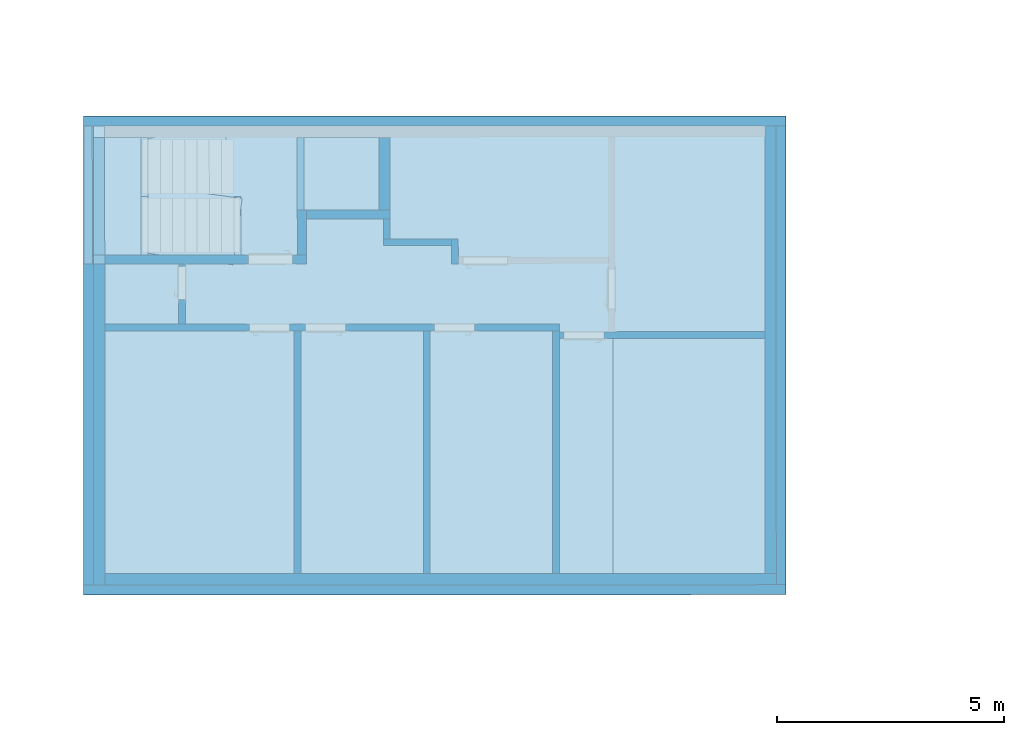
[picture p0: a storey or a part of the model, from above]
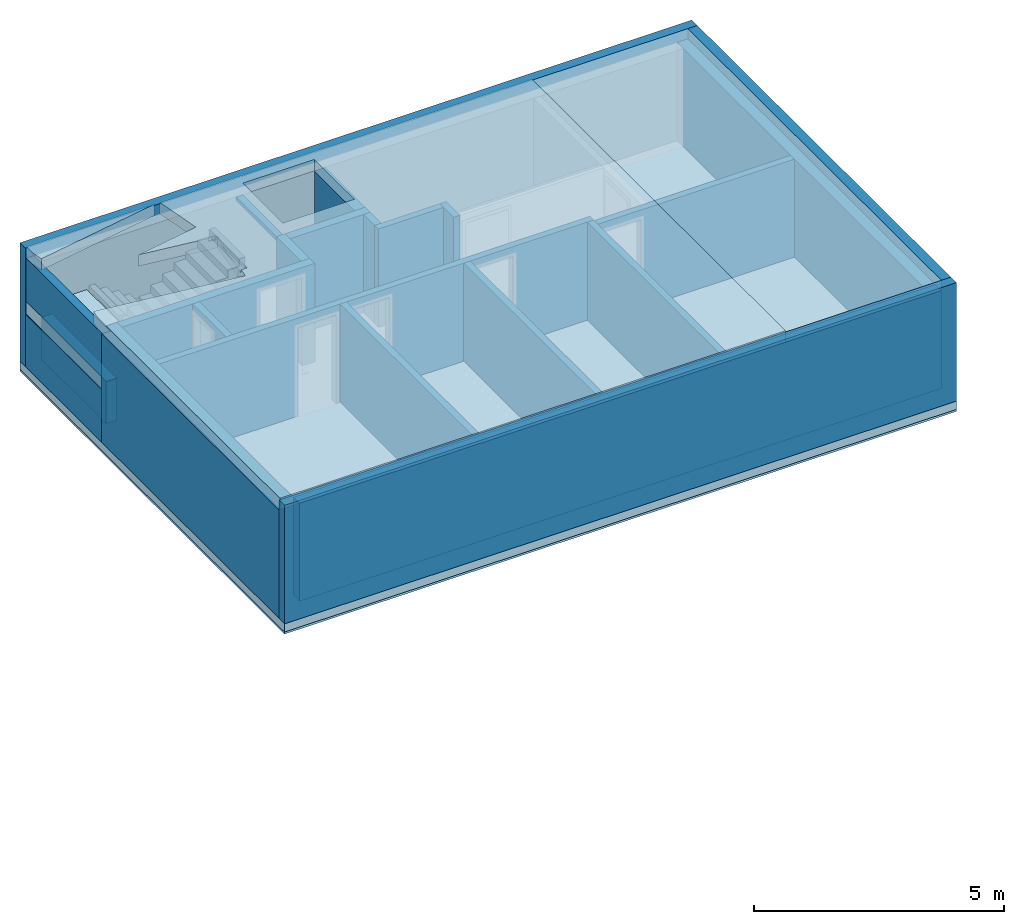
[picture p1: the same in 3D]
Properties of the parts of a building model (IFC2X3), part 1 of 2

# File
Description: no view
File name: I.ifc
Time: 2026-08-27T15:51:39
Author: Besar Asani
Organization: No Organization
Written by: ODA SDAI 25.4
Authorization: b.asani

# IfcProject, 00'000 - Besar Asani
AllplanAttributes - Bauherr: Bauherr Name; Architekt: Architekt Name; Bauort: PLZ und Ort; Bauunternehmer Straße: Bauunternehmer Strasse; Bauunternehmer Plz/Ort: Bauunternehmer PLZ Ort; Bauherr Straße: Bauherr Strasse; Bauherr Plz/Ort: Bauherr PLZ Ort; Architekt Straße: Architekt Strasse; Architekt Plz/Ort: Architekt PLZ Ort; Projektbeschreibung: Projektbeschreibung; Bauunternehmer: Bauunternehmer Name

# IfcSite, Modelle auf dem Nullpunkt
RefLatitude: 48, 8, 10, 320000; RefLongitude: 11, 41, 19, 320000

# IfcBuildingStorey (5)
In: I
Elevation: 0 m
Name
UG
EG
1.OG
2.OG
3.OG

# IfcBeam (29)
AllplanAttributes - 2D Interaktion: yes; Aussenbauteil: yes; Attributset-Objekt: Beam; Abrechnungsart: m³; Objektname: Unterzug
BeamCommon - Status: Neubau
Pset_BeamCommon - LoadBearing: yes
Name | In | Material = AllplanAttributes, Material = Traduction matériau | Gewerk | Allright_Bauteil_ID
 | UG | Béton | Betonarbeiten | 7503Unz0000000245
 | 3.OG | Bois | Zimmer- und Holzbauarbeiten | 7507Unz0000000322
 | 3.OG | Bois | Zimmer- und Holzbauarbeiten | 7507Unz0000000292
 | 3.OG | Bois | Zimmer- und Holzbauarbeiten | 7507Unz0000000282
 | 3.OG | Bois | Zimmer- und Holzbauarbeiten | 7507Unz0000000326
 | 3.OG | Bois | Zimmer- und Holzbauarbeiten | 7507Unz0000000276
 | 3.OG | Bois | Zimmer- und Holzbauarbeiten | 7507Unz0000000314
 | 3.OG | Bois | Zimmer- und Holzbauarbeiten | 7507Unz0000000316
 | 3.OG | Bois | Zimmer- und Holzbauarbeiten | 7507Unz0000000310
 | 3.OG | Bois | Zimmer- und Holzbauarbeiten | 7507Unz0000000272
 | 3.OG | Bois | Zimmer- und Holzbauarbeiten | 7507Unz0000000274
 | 3.OG | Bois | Zimmer- und Holzbauarbeiten | 7507Unz0000000300
 | 3.OG | Bois | Zimmer- und Holzbauarbeiten | 7507Unz0000000280
 | 3.OG | Bois | Zimmer- und Holzbauarbeiten | 7507Unz0000000286
 | 3.OG | Béton | Betonarbeiten | 7507Unz0000000324
 | 3.OG | Bois | Zimmer- und Holzbauarbeiten | 7507Unz0000000306
 | 3.OG | Bois | Zimmer- und Holzbauarbeiten | 7507Unz0000000318
 | 3.OG | Bois | Zimmer- und Holzbauarbeiten | 7507Unz0000000312
 | 3.OG | Bois | Zimmer- und Holzbauarbeiten | 7507Unz0000000320
 | 3.OG | Bois | Zimmer- und Holzbauarbeiten | 7507Unz0000000296
 | 3.OG | Bois | Zimmer- und Holzbauarbeiten | 7507Unz0000000290
 | 3.OG | Bois | Zimmer- und Holzbauarbeiten | 7507Unz0000000308
 | 3.OG | Bois | Zimmer- und Holzbauarbeiten | 7507Unz0000000284
 | 3.OG | Bois | Zimmer- und Holzbauarbeiten | 7507Unz0000000278
 | 3.OG | Bois | Zimmer- und Holzbauarbeiten | 7507Unz0000000270
 | 3.OG | Bois | Zimmer- und Holzbauarbeiten | 7507Unz0000000304
 | 3.OG | Bois | Zimmer- und Holzbauarbeiten | 7507Unz0000000298
 | 3.OG | Bois | Zimmer- und Holzbauarbeiten | 7507Unz0000000294
 | 3.OG | Bois | Zimmer- und Holzbauarbeiten | 7507Unz0000000288

# IfcBuildingElementProxy (68)
Name | In | Objektname | Bezeichnung | Attributset-Objekt | Allright_Bauteil_ID | Abrechnungsart | V6 (m) = V7 (m) = V8 (m) = V9 | Programmversion | Plugin_Bezeichnung | Plugin_Objektname | Glasanteil_berücksichtigen | Version | Abrechnungsart (2) | GlassSurface | HeightWindowSillOutside | HeightWindowSillInside | OffsetOpeningBottom = OffsetOpeningTop = OffsetOpeningLeft = OffsetOpeningRight | DeductionOpeningBottom | DeductionOpeningLeft | DeductionOpeningRight | DeductionOpeningTop
Kontrollpunkt | UG | Kontrollpunkt | Kontrollpunkt | Body | 7503Kop0000000006 | m³ | AllplanAttributes - Text1: X = 2695881.75; Text2: Y = 1261014.30; Typ: Kontrollpunkt; Elementbezeichnung: Kontrollpunkt; Barrierefrei: no; öffentlich zugänglich: no; BuildingElementProxyCommon - Status: Neubau; Tragendes Bauteil: no
Kontrollpunkt | UG | Kontrollpunkt | Kontrollpunkt | Body | 7503Kop0000000008 | m³ | AllplanAttributes - Text1: X = 2695833.95; Text2: Y = 1261009.75; Typ: Kontrollpunkt; Elementbezeichnung: Kontrollpunkt; Barrierefrei: no; öffentlich zugänglich: no; X_Koordinate: 0 m; Y_Koordinate: 0 m; Achsenendpunkt (X): 0 m; BuildingElementProxyCommon - Status: Neubau; Tragendes Bauteil: no
1flg Weiß UZ außen | UG | Türmakro, -SmartPart | 1flg Weiß UZ außen | Door | 7503Mak0000000034 | St | 0 | 3.0 | MainObject | SmartPartCompressed | 0 | 8.0 | St | 0 | 0 | 0 | 0 | 0 | 20 | 20 | 20 | AllplanAttributes - Behindertengerecht: no; Selbstschliessend: no; DoorCommon - Rauchschutz: no; Notausgang: no; Antrieb: no
1flg Weiß UZ außen | UG | Türmakro, -SmartPart | 1flg Weiß UZ außen | Door | 7503Mak0000000064 | St | 0 | 3.0 | MainObject | SmartPartCompressed | 0 | 8.0 | St | 0 | 0 | 0 | 0 | 0 | 20 | 20 | 20 | AllplanAttributes - Behindertengerecht: no; Selbstschliessend: no; DoorCommon - Rauchschutz: no; Notausgang: no; Antrieb: no
1flg Weiß UZ außen | UG | Türmakro, -SmartPart | 1flg Weiß UZ außen | Door | 7503Mak0000000097 | St | 0 | 3.0 | MainObject | SmartPartCompressed | 0 | 8.0 | St | 0 | 0 | 0 | 0 | 0 | 20 | 20 | 20 | AllplanAttributes - Behindertengerecht: no; Selbstschliessend: no; DoorCommon - Rauchschutz: no; Notausgang: no; Antrieb: no
1flg Weiß UZ außen | UG | Türmakro, -SmartPart | 1flg Weiß UZ außen | Door | 7503Mak0000000138 | St | 0 | 3.0 | MainObject | SmartPartCompressed | 0 | 8.0 | St | 0 | 0 | 0 | 0 | 0 | 20 | 20 | 20 | AllplanAttributes - Behindertengerecht: no; Selbstschliessend: no; DoorCommon - Rauchschutz: no; Notausgang: no; Antrieb: no
1flg Weiß UZ außen | UG | Türmakro, -SmartPart | 1flg Weiß UZ außen | Door | 7503Mak0000000157 | St | 0 | 3.0 | MainObject | SmartPartCompressed | 0 | 8.0 | St | 0 | 0 | 0 | 0 | 0 | 20 | 20 | 20 | AllplanAttributes - Behindertengerecht: no; Selbstschliessend: no; DoorCommon - Rauchschutz: no; Notausgang: no; Antrieb: no
1flg Weiß UZ außen | UG | Türmakro, -SmartPart | 1flg Weiß UZ außen | Door | 7503Mak0000000176 | St | 0 | 3.0 | MainObject | SmartPartCompressed | 0 | 8.0 | St | 0 | 0 | 0 | 0 | 0 | 20 | 20 | 20 | AllplanAttributes - Behindertengerecht: no; Selbstschliessend: no; DoorCommon - Rauchschutz: no; Notausgang: no; Antrieb: no
1flg Weiß UZ außen | UG | Türmakro, -SmartPart | 1flg Weiß UZ außen | Door | 7503Mak0000000197 | St | 0 | 3.0 | MainObject | SmartPartCompressed | 0 | 8.0 | St | 0 | 0 | 0 | 0 | 0 | 20 | 20 | 20 | AllplanAttributes - Behindertengerecht: no; Selbstschliessend: no; DoorCommon - Rauchschutz: no; Notausgang: no; Antrieb: no
1flg Weiß UZ außen | UG | Türmakro, -SmartPart | 1flg Weiß UZ außen | Door | 7503Mak0000000221 | St | 0 | 3.0 | MainObject | SmartPartCompressed | 0 | 8.0 | St | 0 | 0 | 0 | 0 | 0 | 20 | 20 | 20 | AllplanAttributes - Behindertengerecht: no; Selbstschliessend: no; DoorCommon - Rauchschutz: no; Notausgang: no; Antrieb: no
 | UG | Mengenkörper |  | Body | 7503Kop0000000226 | m³
 | UG | Mengenkörper |  | Body | 7503Kop0000000228 | m³
 | UG | Mengenkörper |  | Body | 7503Kop0000000230 | m³
 | UG | Mengenkörper |  | Body | 7503Kop0000000232 | m³
1flg Weiß Oberlicht | EG | Türmakro, -SmartPart | 1flg Weiß Oberlicht | Door | 7504Mak0000000036 | St | 0 | 3.0 | MainObject | SmartPartCompressed | 0 | 8.0 | St | 2.02 | 0 | 0 | 0 | 250 | 120 | 120 | 100 | AllplanAttributes - Behindertengerecht: no; Selbstschliessend: no; DoorCommon - Rauchschutz: no; Notausgang: no; Antrieb: no
2flg Weiß Stulp | EG | Fenstermakro, -SmartPart | 2flg Weiß Stulp | Window | 7504Mak0000000062 | St | 0 | 3.0 | MainObject | SmartPartCompressed | 100 | 8.0 | St | 1.67895 | 150 | 30 | 0 | 70 | 70 | 70 | 70 | AllplanAttributes - Fensterbank aussen: no; WindowCommon - Rauchschutz: no; Notausgang: no; Antrieb: no; Fensterbank innen: no
1flg Weiß UZ außen | EG | Türmakro, -SmartPart | 1flg Weiß UZ außen | Door | 7504Mak0000000115 | St | 0 | 3.0 | MainObject | SmartPartCompressed | 0 | 8.0 | St | 0 | 0 | 0 | 0 | 0 | 20 | 20 | 20 | AllplanAttributes - Behindertengerecht: no; Selbstschliessend: no; DoorCommon - Rauchschutz: no; Notausgang: no; Antrieb: no
2flg Weiß Stulp | EG | Fenstermakro, -SmartPart | 2flg Weiß Stulp | Window | 7504Mak0000000141 | St | 0 | 3.0 | MainObject | SmartPartCompressed | 100 | 8.0 | St | 2.14047 | 130 | 30 | 0 | 150 | 70 | 70 | 150 | AllplanAttributes - Fensterbank aussen: no; WindowCommon - Rauchschutz: no; Notausgang: no; Antrieb: no; Fensterbank innen: no
2flg Weiß Stulp | EG | Fenstermakro, -SmartPart | 2flg Weiß Stulp | Window | 7504Mak0000000165 | St | 0 | 3.0 | MainObject | SmartPartCompressed | 100 | 8.0 | St | 2.14047 | 130 | 30 | 0 | 150 | 70 | 70 | 150 | AllplanAttributes - Fensterbank aussen: no; WindowCommon - Rauchschutz: no; Notausgang: no; Antrieb: no; Fensterbank innen: no
1flg Weiß UZ außen | EG | Türmakro, -SmartPart | 1flg Weiß UZ außen | Door | 7504Mak0000000221 | St | 0 | 3.0 | MainObject | SmartPartCompressed | 0 | 8.0 | St | 0 | 0 | 0 | 0 | 0 | 20 | 20 | 20 | AllplanAttributes - Behindertengerecht: no; Selbstschliessend: no; DoorCommon - Rauchschutz: no; Notausgang: no; Antrieb: no
1flg Weiß UZ außen | EG | Türmakro, -SmartPart | 1flg Weiß UZ außen | Door | 7504Mak0000000242 | St | 0 | 3.0 | MainObject | SmartPartCompressed | 0 | 8.0 | St | 0 | 0 | 0 | 0 | 0 | 20 | 20 | 20 | AllplanAttributes - Behindertengerecht: no; Selbstschliessend: no; DoorCommon - Rauchschutz: no; Notausgang: no; Antrieb: no
1flg Weiß UZ außen | EG | Türmakro, -SmartPart | 1flg Weiß UZ außen | Door | 7504Mak0000000261 | St | 0 | 3.0 | MainObject | SmartPartCompressed | 0 | 8.0 | St | 0 | 0 | 0 | 0 | 0 | 20 | 20 | 20 | AllplanAttributes - Behindertengerecht: no; Selbstschliessend: no; DoorCommon - Rauchschutz: no; Notausgang: no; Antrieb: no
1flg Weiß UZ außen | EG | Türmakro, -SmartPart | 1flg Weiß UZ außen | Door | 7504Mak0000000282 | St | 0 | 3.0 | MainObject | SmartPartCompressed | 0 | 8.0 | St | 0 | 0 | 0 | 0 | 0 | 20 | 20 | 20 | AllplanAttributes - Behindertengerecht: no; Selbstschliessend: no; DoorCommon - Rauchschutz: no; Notausgang: no; Antrieb: no
2flg Weiß Stulp | EG | Fenstermakro, -SmartPart | 2flg Weiß Stulp | Window | 7504Mak0000000314 | St | 0 | 3.0 | MainObject | SmartPartCompressed | 100 | 8.0 | St | 2.8788 | 150 | 30 | 0 | 70 | 70 | 70 | 70 | AllplanAttributes - Fensterbank aussen: no; WindowCommon - Rauchschutz: no; Notausgang: no; Antrieb: no; Fensterbank innen: no
 | EG | Mengenkörper |  | Body | 7504Kop0000000324 | m³
 | EG | Mengenkörper |  | Body | 7504Kop0000000326 | m³
 | EG | Mengenkörper |  | Body | 7504Kop0000000328 | m³
 | EG | Mengenkörper |  | Body | 7504Kop0000000330 | m³
 | EG | Mengenkörper |  | Body | 7504Kop0000000335 | m³
2flg Weiß Stulp | 1.OG | Fenstermakro, -SmartPart | 2flg Weiß Stulp | Window | 7505Mak0000000021 | St | 0 | 3.0 | MainObject | SmartPartCompressed | 100 | 8.0 | St | 0.63443 | 0 | 0 | 0 | 150 | 150 | 150 | 150 | AllplanAttributes - Fensterbank aussen: no; WindowCommon - Rauchschutz: no; Notausgang: no; Antrieb: no; Fensterbank innen: no
2flg Weiß Stulp | 1.OG | Fenstermakro, -SmartPart | 2flg Weiß Stulp | Window | 7505Mak0000000047 | St | 0 | 3.0 | MainObject | SmartPartCompressed | 100 | 8.0 | St | 1.31118 | 130 | 30 | 0 | 150 | 70 | 70 | 210 | AllplanAttributes - Fensterbank aussen: no; WindowCommon - Rauchschutz: no; Notausgang: no; Antrieb: no; Fensterbank innen: no
1flg Weiß UZ außen | 1.OG | Türmakro, -SmartPart | 1flg Weiß UZ außen | Door | 7505Mak0000000091 | St | 0 | 3.0 | MainObject | SmartPartCompressed | 0 | 8.0 | St | 0 | 0 | 0 | 0 | 0 | 20 | 20 | 20 | AllplanAttributes - Behindertengerecht: no; Selbstschliessend: no; DoorCommon - Rauchschutz: no; Notausgang: no; Antrieb: no
1flg Weiß UZ außen | 1.OG | Türmakro, -SmartPart | 1flg Weiß UZ außen | Door | 7505Mak0000000121 | St | 0 | 3.0 | MainObject | SmartPartCompressed | 0 | 8.0 | St | 0 | 0 | 0 | 0 | 0 | 20 | 20 | 20 | AllplanAttributes - Behindertengerecht: no; Selbstschliessend: no; DoorCommon - Rauchschutz: no; Notausgang: no; Antrieb: no
1flg Weiß UZ außen | 1.OG | Türmakro, -SmartPart | 1flg Weiß UZ außen | Door | 7505Mak0000000142 | St | 0 | 3.0 | MainObject | SmartPartCompressed | 0 | 8.0 | St | 0 | 0 | 0 | 0 | 0 | 20 | 20 | 20 | AllplanAttributes - Behindertengerecht: no; Selbstschliessend: no; DoorCommon - Rauchschutz: no; Notausgang: no; Antrieb: no
1flg Weiß UZ außen | 1.OG | Türmakro, -SmartPart | 1flg Weiß UZ außen | Door | 7505Mak0000000178 | St | 0 | 3.0 | MainObject | SmartPartCompressed | 0 | 8.0 | St | 0 | 0 | 0 | 0 | 0 | 20 | 20 | 20 | AllplanAttributes - Behindertengerecht: no; Selbstschliessend: no; DoorCommon - Rauchschutz: no; Notausgang: no; Antrieb: no
1flg Weiß UZ außen | 1.OG | Türmakro, -SmartPart | 1flg Weiß UZ außen | Door | 7505Mak0000000197 | St | 0 | 3.0 | MainObject | SmartPartCompressed | 0 | 8.0 | St | 0 | 0 | 0 | 0 | 0 | 20 | 20 | 20 | AllplanAttributes - Behindertengerecht: no; Selbstschliessend: no; DoorCommon - Rauchschutz: no; Notausgang: no; Antrieb: no
2flg Weiß Stulp | 1.OG | Fenstermakro, -SmartPart | 2flg Weiß Stulp | Window | 7505Mak0000000223 | St | 0 | 3.0 | MainObject | SmartPartCompressed | 100 | 8.0 | St | 2.29779 | 130 | 30 | 0 | 150 | 70 | 70 | 220 | AllplanAttributes - Fensterbank aussen: no; WindowCommon - Rauchschutz: no; Notausgang: no; Antrieb: no; Fensterbank innen: no
2flg Weiß Stulp | 1.OG | Fenstermakro, -SmartPart | 2flg Weiß Stulp | Window | 7505Mak0000000247 | St | 0 | 3.0 | MainObject | SmartPartCompressed | 100 | 8.0 | St | 2.29779 | 130 | 30 | 0 | 150 | 70 | 70 | 220 | AllplanAttributes - Fensterbank aussen: no; WindowCommon - Rauchschutz: no; Notausgang: no; Antrieb: no; Fensterbank innen: no
2flg Weiß Stulp | 1.OG | Fenstermakro, -SmartPart | 2flg Weiß Stulp | Door | 7505Mak0000000271 | St | 0 | 3.0 | MainObject | SmartPartCompressed | 100 | 8.0 | St | 2.29779 | 130 | 30 | 0 | 150 | 70 | 70 | 220 | DoorCommon - Rauchschutz: no; Notausgang: no; Antrieb: no; AllplanAttributes - Fensterbank außen: no; Fensterbank innen: no
1flg Weiß Blockzarge | 1.OG | Fenstermakro, -SmartPart | 1flg Weiß Blockzarge | Window | 7505Mak0000000302 | St | 0 | 3.0 | MainObject | SmartPartCompressed | 0 | 8.0 | St | 6.9847 | 0 | 0 | 0 | 0 | 70 | 70 | 70 | AllplanAttributes - Barrierefrei: no; Selbstschließend: no; WindowCommon - Rauchschutz: no; Notausgang: no; Antrieb: no
 | 1.OG | Mengenkörper |  | Body | 7505Kop0000000310 | m³
 | 1.OG | Mengenkörper |  | Body | 7505Kop0000000312 | m³
 | 1.OG | Mengenkörper |  | Body | 7505Kop0000000314 | m³
 | 1.OG | Mengenkörper |  | Body | 7505Kop0000000316 | m³
1flg Weiß UZ außen | 2.OG | Türmakro, -SmartPart | 1flg Weiß UZ außen | Door | 7506Mak0000000054 | St | 0 | 3.0 | MainObject | SmartPartCompressed | 0 | 8.0 | St | 0 | 0 | 0 | 0 | 0 | 20 | 20 | 20 | AllplanAttributes - Behindertengerecht: no; Selbstschliessend: no; DoorCommon - Rauchschutz: no; Notausgang: no; Antrieb: no
1flg Weiß UZ außen | 2.OG | Türmakro, -SmartPart | 1flg Weiß UZ außen | Door | 7506Mak0000000081 | St | 0 | 3.0 | MainObject | SmartPartCompressed | 0 | 8.0 | St | 0 | 0 | 0 | 0 | 0 | 20 | 20 | 20 | AllplanAttributes - Behindertengerecht: no; Selbstschliessend: no; DoorCommon - Rauchschutz: no; Notausgang: no; Antrieb: no
1flg Weiß UZ außen | 2.OG | Türmakro, -SmartPart | 1flg Weiß UZ außen | Door | 7506Mak0000000102 | St | 0 | 3.0 | MainObject | SmartPartCompressed | 0 | 8.0 | St | 0 | 0 | 0 | 0 | 0 | 20 | 20 | 20 | AllplanAttributes - Behindertengerecht: no; Selbstschliessend: no; DoorCommon - Rauchschutz: no; Notausgang: no; Antrieb: no
1flg Weiß UZ außen | 2.OG | Türmakro, -SmartPart | 1flg Weiß UZ außen | Door | 7506Mak0000000135 | St | 0 | 3.0 | MainObject | SmartPartCompressed | 0 | 8.0 | St | 0 | 0 | 0 | 0 | 0 | 20 | 20 | 20 | AllplanAttributes - Behindertengerecht: no; Selbstschliessend: no; DoorCommon - Rauchschutz: no; Notausgang: no; Antrieb: no
1flg Weiß UZ außen | 2.OG | Türmakro, -SmartPart | 1flg Weiß UZ außen | Door | 7506Mak0000000154 | St | 0 | 3.0 | MainObject | SmartPartCompressed | 0 | 8.0 | St | 0 | 0 | 0 | 0 | 0 | 20 | 20 | 20 | AllplanAttributes - Behindertengerecht: no; Selbstschliessend: no; DoorCommon - Rauchschutz: no; Notausgang: no; Antrieb: no
2flg Weiß Stulp | 2.OG | Fenstermakro, -SmartPart | 2flg Weiß Stulp | Window | 7506Mak0000000180 | St | 0 | 3.0 | MainObject | SmartPartCompressed | 100 | 8.0 | St | 1.31118 | 130 | 30 | 0 | 150 | 70 | 70 | 210 | AllplanAttributes - Fensterbank aussen: no; WindowCommon - Rauchschutz: no; Notausgang: no; Antrieb: no; Fensterbank innen: no
2flg Weiß Stulp | 2.OG | Fenstermakro, -SmartPart | 2flg Weiß Stulp | Window | 7506Mak0000000206 | St | 0 | 3.0 | MainObject | SmartPartCompressed | 100 | 8.0 | St | 2.2788 | 130 | 30 | 0 | 150 | 70 | 70 | 230 | AllplanAttributes - Fensterbank aussen: no; WindowCommon - Rauchschutz: no; Notausgang: no; Antrieb: no; Fensterbank innen: no
2flg Weiß Stulp | 2.OG | Fenstermakro, -SmartPart | 2flg Weiß Stulp | Window | 7506Mak0000000230 | St | 0 | 3.0 | MainObject | SmartPartCompressed | 100 | 8.0 | St | 2.2788 | 130 | 30 | 0 | 150 | 70 | 70 | 230 | AllplanAttributes - Fensterbank aussen: no; WindowCommon - Rauchschutz: no; Notausgang: no; Antrieb: no; Fensterbank innen: no
2flg Weiß Stulp | 2.OG | Fenstermakro, -SmartPart | 2flg Weiß Stulp | Door | 7506Mak0000000254 | St | 0 | 3.0 | MainObject | SmartPartCompressed | 100 | 8.0 | St | 2.2788 | 130 | 30 | 0 | 150 | 70 | 70 | 230 | DoorCommon - Rauchschutz: no; Notausgang: no; Antrieb: no; AllplanAttributes - Fensterbank außen: no; Fensterbank innen: no
2flg Weiß Stulp | 2.OG | Fenstermakro, -SmartPart | 2flg Weiß Stulp | Door | 7506Mak0000000285 | St | 0 | 3.0 | MainObject | SmartPartCompressed | 100 | 8.0 | St | 1.2183 | 130 | 30 | 0 | 70 | 70 | 70 | 200 | DoorCommon - Rauchschutz: no; Notausgang: no; Antrieb: no; AllplanAttributes - Fensterbank außen: no; Fensterbank innen: no
1flg Weiß Blockzarge | 2.OG | Fenstermakro, -SmartPart | 1flg Weiß Blockzarge | Window | 7506Mak0000000329 | St | 0 | 3.0 | MainObject | SmartPartCompressed | 0 | 8.0 | St | 6.2837 | 0 | 0 | 0 | 0 | 70 | 70 | 70 | AllplanAttributes - Barrierefrei: no; Selbstschließend: no; WindowCommon - Rauchschutz: no; Notausgang: no; Antrieb: no
 | 2.OG | Mengenkörper |  | Body | 7506Kop0000000340 | m³
 | 2.OG | Mengenkörper |  | Body | 7506Kop0000000342 | m³
 | 2.OG | Mengenkörper |  | Body | 7506Kop0000000347 | m³
 | 2.OG | Mengenkörper |  | Body | 7506Kop0000000349 | m³
1flg Weiß UZ außen | 3.OG | Türmakro, -SmartPart | 1flg Weiß UZ außen | Door | 7507Mak0000000033 | St | 0 | 3.0 | MainObject | SmartPartCompressed | 0 | 8.0 | St | 0 | 0 | 0 | 0 | 0 | 20 | 20 | 20 | AllplanAttributes - Behindertengerecht: no; Selbstschliessend: no; DoorCommon - Rauchschutz: no; Notausgang: no; Antrieb: no
2flg Weiß Stulp | 3.OG | Fenstermakro, -SmartPart | 2flg Weiß Stulp | Window | 7507Mak0000000044 | St | 0 | 3.0 | MainObject | SmartPartCompressed | 100 | 8.0 | St | 0 | 0 | 0 | 0 | 175 | 0 | 350 | 350 | AllplanAttributes - Fensterbank aussen: no; WindowCommon - Rauchschutz: no; Notausgang: no; Antrieb: no; Fensterbank innen: no
2flg Weiß Stulp | 3.OG | Fenstermakro, -SmartPart | 2flg Weiß Stulp | Window | 7507Mak0000000073 | St | 0 | 3.0 | MainObject | SmartPartCompressed | 100 | 8.0 | St | 1.19196 | 130 | 30 | 0 | 120 | 70 | 70 | 220 | AllplanAttributes - Fensterbank aussen: no; WindowCommon - Rauchschutz: no; Notausgang: no; Antrieb: no; Fensterbank innen: no
2flg Weiß Stulp | 3.OG | Fenstermakro, -SmartPart | 2flg Weiß Stulp | Window | 7507Mak0000000119 | St | 0 | 3.0 | MainObject | SmartPartCompressed | 100 | 8.0 | St | 0.6308 | 130 | 30 | 0 | 200 | 120 | 120 | 220 | AllplanAttributes - Fensterbank aussen: no; WindowCommon - Rauchschutz: no; Notausgang: no; Antrieb: no; Fensterbank innen: no
2flg Weiß Stulp | 3.OG | Fenstermakro, -SmartPart | 2flg Weiß Stulp | Window | 7507Mak0000000139 | St | 0 | 3.0 | MainObject | SmartPartCompressed | 100 | 8.0 | St | 1.7596 | 155 | 30 | 0 | 200 | 120 | 120 | 250 | AllplanAttributes - Fensterbank aussen: no; WindowCommon - Rauchschutz: no; Notausgang: no; Antrieb: no; Fensterbank innen: no
1flg Weiß UZ außen | 3.OG | Türmakro, -SmartPart | 1flg Weiß UZ außen | Door | 7507Mak0000000218 | St | 0 | 3.0 | MainObject | SmartPartCompressed | 0 | 8.0 | St | 0 | 0 | 0 | 0 | 80 | 20 | 20 | 20 | AllplanAttributes - Behindertengerecht: no; Selbstschliessend: no; DoorCommon - Rauchschutz: no; Notausgang: no; Antrieb: no
 | 3.OG | Erweitertes Element |  | Body | 7507Kop0000000226 | m³ | AllplanAttributes - Gewerk: Betonarbeiten
1flg Weiß UZ außen | 3.OG | Türmakro, -SmartPart | 1flg Weiß UZ außen | Door | 7507Mak0000000247 | St | 0 | 3.0 | MainObject | SmartPartCompressed | 0 | 8.0 | St | 1.9339 | 0 | 0 | 0 | 0 | 20 | 20 | 20 | AllplanAttributes - Behindertengerecht: no; Selbstschliessend: no; DoorCommon - Rauchschutz: no; Notausgang: no; Antrieb: no
2flg Weiß Stulp | 3.OG | SmartPart | 2flg Weiß Stulp | Body | 7507Mak0000000262 | St | 0 | 3.0 | MainObject | SmartPartCompressed | 100 | 8.0 | St | AllplanAttributes - Fensterbank außen: no; Fensterbank innen: no; Glasfläche: 0; Einbauhöhe_Fensterbank_Außen: 0.13 m; Einbauhöhe_Fensterbank_Innen: 0 m; Abstand_Öffn_Unten: 0 m; Abstand_Öffn_Oben: 0 m; Abstand_Öffn_Links: 0 m; Abstand_Öffn_Rechts: 0 m; Abzug_Öffn_Unten: 0 m; Abzug_Öffn_Links: 0 m; Abzug_Öffn_Rechts: 0 m; Abzug_Öffn_Oben: 0 m; Rauchschutz: no; Notausgang: no; Antrieb: no

# IfcBuildingElementProxy: DOOR (5)
AllplanAttributes - V6: 0 m; V7: 0 m; V8: 0 m; V9: 0; Programmversion: 3.0; Bezeichnung: 1flg Weiß Blockzarge; Plugin_Bezeichnung: MainObject; Plugin_Objektname: SmartPartCompressed; Glasanteil_berücksichtigen: 0; Version: 8.0; Attributset-Objekt: Door; Abrechnungsart (2): St; HeightWindowSillOutside: 0; HeightWindowSillInside: 0; OffsetOpeningBottom: 0; OffsetOpeningTop: 0; OffsetOpeningLeft: 0; OffsetOpeningRight: 0; Behindertengerecht: no; Selbstschliessend: no; Abrechnungsart: St
DoorCommon - Rauchschutz: no; Notausgang: no; Antrieb: no
Name | In | Objektname | GlassSurface | DeductionOpeningBottom | DeductionOpeningLeft = DeductionOpeningRight | DeductionOpeningTop | Allright_Bauteil_ID
1flg Weiß Blockzarge | EG | Türmakro, -SmartPart | 7.1067 | 0 | 70 | 70 | 7504Mak0000000183
1flg Weiß Blockzarge | 2.OG | Fenstermakro, -SmartPart | 1.7765 | 200 | 110 | 220 | 7506Mak0000000311
1flg Weiß Blockzarge | 3.OG | Fenstermakro, -SmartPart | 6.85865 | 0 | 70 | 70 | 7507Mak0000000101
1flg Weiß Blockzarge | 3.OG | Fenstermakro, -SmartPart | 6.56365 | 0 | 70 | 70 | 7507Mak0000000159
1flg Weiß Blockzarge | 3.OG | Fenstermakro, -SmartPart | 6.56365 | 0 | 70 | 70 | 7507Mak0000000177

# IfcOpeningElement: Opening (86)
Pset_OpeningElementCommon - FireExit: no
Name | In | Object Layer Attributes #1, Gewerk | Object Layer Attributes #1, Türanschlag | Object Layer Attributes #1, Objektname | Object Layer Attributes #1, Allright_Bauteil_ID | Object Layer Attributes #1, Abrechnungsart | ProtectedOpening
 | UG | Mauerarbeiten | DIN L | Türöffnung | 7503Köf0000000018 | m³ | no | AllplanAttributes - Object Layer Attributes #1, Versatz_oben: 0; Object Layer Attributes #1, Versatz_unten: 0
 | UG | Betonarbeiten | - | Türöffnung | 7503Köf0000000237 | m³ | AllplanAttributes - Object Layer Attributes #1, Attributset-Objekt: Door; Object Layer Attributes #1, DoorCommon, Barrierefrei: no; Object Layer Attributes #1, DoorCommon, Rauchschutz: no; Object Layer Attributes #1, DoorCommon, Selbstschließend: no; Object Layer Attributes #1, DoorCommon, Antrieb: no
 | UG | Mauerarbeiten | DIN L | Türöffnung | 7503Köf0000000122 | m³ | no | AllplanAttributes - Object Layer Attributes #1, Versatz_oben: 0; Object Layer Attributes #1, Versatz_unten: 0
 | UG | Mauerarbeiten | DIN L | Türöffnung | 7503Köf0000000141 | m³ | no | AllplanAttributes - Object Layer Attributes #1, Versatz_oben: 0; Object Layer Attributes #1, Versatz_unten: 0
 | UG | Mauerarbeiten | DIN R | Türöffnung | 7503Köf0000000160 | m³ | no
 | UG | Mauerarbeiten | DIN L | Türöffnung | 7503Köf0000000048 | m³ | no | AllplanAttributes - Object Layer Attributes #1, Versatz_oben: 0; Object Layer Attributes #1, Versatz_unten: 0
Deckendurchbruch | UG | Betonarbeiten |  | Deckendurchbruch | 7503Das0000000252 | m² | no | AllplanAttributes - Object Layer Attributes #1, Bezeichnung: Deckendurchbruch
Deckendurchbruch | UG | Betonarbeiten |  | Deckendurchbruch | 7503Das0000000251 | m² | no | AllplanAttributes - Object Layer Attributes #1, Bezeichnung: Deckendurchbruch
 | UG | Mauerarbeiten | DIN L | Türöffnung | 7503Köf0000000205 | m³ | no | AllplanAttributes - Object Layer Attributes #1, Versatz_oben: 0; Object Layer Attributes #1, Versatz_unten: 0
 | UG | Betonarbeiten | DIN R | Türöffnung | 7503Köf0000000181 | m³ | AllplanAttributes - Object Layer Attributes #1, Attributset-Objekt: Door; Object Layer Attributes #1, DoorCommon, Barrierefrei: no; Object Layer Attributes #1, DoorCommon, Rauchschutz: no; Object Layer Attributes #1, DoorCommon, Selbstschließend: no; Object Layer Attributes #1, DoorCommon, Antrieb: no
 | UG | Mauerarbeiten | DIN R | Türöffnung | 7503Köf0000000081 | m³ | no | AllplanAttributes - Object Layer Attributes #1, Versatz_oben: 0; Object Layer Attributes #1, Versatz_unten: 0
 | EG | Betonarbeiten | DIN R | Türöffnung | 7504Köf0000000017 | m³ | AllplanAttributes - Object Layer Attributes #1, Attributset-Objekt: Door; Object Layer Attributes #1, DoorCommon, Barrierefrei: no; Object Layer Attributes #1, DoorCommon, Rauchschutz: no; Object Layer Attributes #1, DoorCommon, Selbstschließend: no; Object Layer Attributes #1, DoorCommon, Antrieb: no
 | EG | Wärme- und Kältedämmarbeiten |  | Fensteröffnung | 7504Köf0000000319 | m² | no
 | EG | Betonarbeiten | - | Türöffnung | 7504Köf0000000006 | m³ | AllplanAttributes - Object Layer Attributes #1, Attributset-Objekt: Door; Object Layer Attributes #1, DoorCommon, Barrierefrei: no; Object Layer Attributes #1, DoorCommon, Rauchschutz: no; Object Layer Attributes #1, DoorCommon, Selbstschließend: no; Object Layer Attributes #1, DoorCommon, Antrieb: no
 | EG | Betonarbeiten |  | Fensteröffnung | 7504Köf0000000293 | m³ | no
 | EG | Mauerarbeiten |  | Fensteröffnung | 7504Köf0000000041 | m³ | no
 | EG | Wärme- und Kältedämmarbeiten |  | Fensteröffnung | 7504Köf0000000082 | m² | no
 | EG | Betonarbeiten | - | Türöffnung | 7504Köf0000000085 | m² | AllplanAttributes - Object Layer Attributes #1, Attributset-Objekt: Door; Object Layer Attributes #1, DoorCommon, Barrierefrei: no; Object Layer Attributes #1, DoorCommon, Rauchschutz: no; Object Layer Attributes #1, DoorCommon, Selbstschließend: no; Object Layer Attributes #1, DoorCommon, Antrieb: no
 | EG | Mauerarbeiten | DIN R | Türöffnung | 7504Köf0000000205 | m³ | no | AllplanAttributes - Object Layer Attributes #1, Versatz_oben: 0; Object Layer Attributes #1, Versatz_unten: 0
 | EG | Mauerarbeiten |  | Fensteröffnung | 7504Köf0000000120 | m³ | no
 | EG | Mauerarbeiten |  | Fensteröffnung | 7504Köf0000000144 | m³ | no
 | EG | Betonarbeiten | DIN L | Türöffnung | 7504Köf0000000168 | m³ | AllplanAttributes - Object Layer Attributes #1, Attributset-Objekt: Door; Object Layer Attributes #1, DoorCommon, Barrierefrei: no; Object Layer Attributes #1, DoorCommon, Rauchschutz: no; Object Layer Attributes #1, DoorCommon, Selbstschließend: no; Object Layer Attributes #1, DoorCommon, Antrieb: no
 | EG | Mauerarbeiten | DIN L | Türöffnung | 7504Köf0000000099 | m³ | no | AllplanAttributes - Object Layer Attributes #1, Versatz_oben: 0; Object Layer Attributes #1, Versatz_unten: 0
 | EG | Wärme- und Kältedämmarbeiten |  | Fensteröffnung | 7504Köf0000000188 | m² | no
 | EG | Wärme- und Kältedämmarbeiten |  | Fensteröffnung | 7504Köf0000000191 | m² | no
 | EG | Betonarbeiten | - | Türöffnung | 7504Köf0000000194 | m² | AllplanAttributes - Object Layer Attributes #1, Attributset-Objekt: Door; Object Layer Attributes #1, DoorCommon, Barrierefrei: no; Object Layer Attributes #1, DoorCommon, Rauchschutz: no; Object Layer Attributes #1, DoorCommon, Selbstschließend: no; Object Layer Attributes #1, DoorCommon, Antrieb: no
 | EG | Mauerarbeiten | DIN L | Türöffnung | 7504Köf0000000226 | m³ | no | AllplanAttributes - Object Layer Attributes #1, Versatz_oben: 0; Object Layer Attributes #1, Versatz_unten: 0
 | EG | Mauerarbeiten | DIN L | Türöffnung | 7504Köf0000000245 | m³ | no | AllplanAttributes - Object Layer Attributes #1, Versatz_oben: 0; Object Layer Attributes #1, Versatz_unten: 0
Deckendurchbruch | EG | Betonarbeiten |  | Deckendurchbruch | 7504Das0000000350 | m² | no | AllplanAttributes - Object Layer Attributes #1, Bezeichnung: Deckendurchbruch
Deckendurchbruch | EG | Betonarbeiten |  | Deckendurchbruch | 7504Das0000000349 | m² | no | AllplanAttributes - Object Layer Attributes #1, Bezeichnung: Deckendurchbruch
 | EG | Betonarbeiten | DIN L | Türöffnung | 7504Köf0000000266 | m³ | AllplanAttributes - Object Layer Attributes #1, Attributset-Objekt: Door; Object Layer Attributes #1, DoorCommon, Barrierefrei: no; Object Layer Attributes #1, DoorCommon, Rauchschutz: no; Object Layer Attributes #1, DoorCommon, Selbstschließend: no; Object Layer Attributes #1, DoorCommon, Antrieb: no
 | 1.OG | Mauerarbeiten | DIN L | Türöffnung | 7505Köf0000000126 | m³ | no | AllplanAttributes - Object Layer Attributes #1, Versatz_oben: 0; Object Layer Attributes #1, Versatz_unten: 0
 | 1.OG | Betonarbeiten | DIN L | Türöffnung | 7505Köf0000000075 | m³ | AllplanAttributes - Object Layer Attributes #1, Attributset-Objekt: Door; Object Layer Attributes #1, DoorCommon, Barrierefrei: no; Object Layer Attributes #1, DoorCommon, Rauchschutz: no; Object Layer Attributes #1, DoorCommon, Selbstschließend: no; Object Layer Attributes #1, DoorCommon, Antrieb: no
 | 1.OG | Betonarbeiten |  | Fensteröffnung | 7505Köf0000000017 | m³ | no
 | 1.OG | Betonarbeiten | - | Türöffnung | 7505Köf0000000006 | m³ | AllplanAttributes - Object Layer Attributes #1, Attributset-Objekt: Door; Object Layer Attributes #1, DoorCommon, Barrierefrei: no; Object Layer Attributes #1, DoorCommon, Rauchschutz: no; Object Layer Attributes #1, DoorCommon, Selbstschließend: no; Object Layer Attributes #1, DoorCommon, Antrieb: no
 | 1.OG | Mauerarbeiten | DIN L | Türöffnung | 7505Köf0000000162 | m³ | no | AllplanAttributes - Object Layer Attributes #1, Versatz_oben: 0; Object Layer Attributes #1, Versatz_unten: 0
 | 1.OG | Mauerarbeiten | DIN L | Türöffnung | 7505Köf0000000181 | m³ | no | AllplanAttributes - Object Layer Attributes #1, Versatz_oben: 0; Object Layer Attributes #1, Versatz_unten: 0
 | 1.OG | Wärme- und Kältedämmarbeiten |  | Fensteröffnung | 7505Köf0000000067 | m² | no
 | 1.OG | Wärme- und Kältedämmarbeiten |  | Fensteröffnung | 7505Köf0000000070 | m² | no
Deckendurchbruch | 1.OG | Betonarbeiten |  | Deckendurchbruch | 7505Das0000000326 | m² | no | AllplanAttributes - Object Layer Attributes #1, Bezeichnung: Deckendurchbruch
Deckendurchbruch | 1.OG | Betonarbeiten |  | Deckendurchbruch | 7505Das0000000325 | m² | no | AllplanAttributes - Object Layer Attributes #1, Bezeichnung: Deckendurchbruch
 | 1.OG | Mauerarbeiten |  | Fensteröffnung | 7505Köf0000000026 | m³ | no
 | 1.OG | Mauerarbeiten |  | Fensteröffnung | 7505Köf0000000202 | m³ | no
 | 1.OG | Mauerarbeiten |  | Fensteröffnung | 7505Köf0000000226 | m³ | no
 | 1.OG | Betonarbeiten | - | Türöffnung | 7505Köf0000000250 | m³ | AllplanAttributes - Object Layer Attributes #1, Attributset-Objekt: Door; Object Layer Attributes #1, DoorCommon, Barrierefrei: no; Object Layer Attributes #1, DoorCommon, Rauchschutz: no; Object Layer Attributes #1, DoorCommon, Selbstschließend: no; Object Layer Attributes #1, DoorCommon, Antrieb: no
 | 1.OG | Betonarbeiten |  | Fensteröffnung | 7505Köf0000000287 | m³ | no
 | 1.OG | Mauerarbeiten | DIN R | Türöffnung | 7505Köf0000000105 | m³ | no | AllplanAttributes - Object Layer Attributes #1, Versatz_oben: 0; Object Layer Attributes #1, Versatz_unten: 0
 | 1.OG | Wärme- und Kältedämmarbeiten |  | Fensteröffnung | 7505Köf0000000276 | m² | no
 | 1.OG | Wärme- und Kältedämmarbeiten |  | Fensteröffnung | 7505Köf0000000279 | m² | no
 | 1.OG | Betonarbeiten | - | Türöffnung | 7505Köf0000000282 | m² | AllplanAttributes - Object Layer Attributes #1, Attributset-Objekt: Door; Object Layer Attributes #1, DoorCommon, Barrierefrei: no; Object Layer Attributes #1, DoorCommon, Rauchschutz: no; Object Layer Attributes #1, DoorCommon, Selbstschließend: no; Object Layer Attributes #1, DoorCommon, Antrieb: no
 | 2.OG | Betonarbeiten | DIN L | Türöffnung | 7506Köf0000000038 | m³ | AllplanAttributes - Object Layer Attributes #1, Attributset-Objekt: Door; Object Layer Attributes #1, DoorCommon, Barrierefrei: no; Object Layer Attributes #1, DoorCommon, Rauchschutz: no; Object Layer Attributes #1, DoorCommon, Selbstschließend: no; Object Layer Attributes #1, DoorCommon, Antrieb: no
 | 2.OG | Mauerarbeiten | DIN L | Türöffnung | 7506Köf0000000119 | m³ | no | AllplanAttributes - Object Layer Attributes #1, Versatz_oben: 0; Object Layer Attributes #1, Versatz_unten: 0
 | 2.OG | Mauerarbeiten | DIN L | Türöffnung | 7506Köf0000000138 | m³ | no | AllplanAttributes - Object Layer Attributes #1, Versatz_oben: 0; Object Layer Attributes #1, Versatz_unten: 0
 | 2.OG | Mauerarbeiten |  | Fensteröffnung | 7506Köf0000000159 | m³ | no
Deckendurchbruch | 2.OG | Betonarbeiten |  | Deckendurchbruch | 7506Das0000000358 | m² | no | AllplanAttributes - Object Layer Attributes #1, Bezeichnung: Deckendurchbruch
Deckendurchbruch | 2.OG | Betonarbeiten |  | Deckendurchbruch | 7506Das0000000357 | m² | no | AllplanAttributes - Object Layer Attributes #1, Bezeichnung: Deckendurchbruch
 | 2.OG | Mauerarbeiten |  | Fensteröffnung | 7506Köf0000000185 | m³ | no | AllplanAttributes - Object Layer Attributes #1, Versatz_oben: 0; Object Layer Attributes #1, Versatz_unten: 0
 | 2.OG | Mauerarbeiten |  | Fensteröffnung | 7506Köf0000000209 | m³ | no | AllplanAttributes - Object Layer Attributes #1, Versatz_oben: 0; Object Layer Attributes #1, Versatz_unten: 0
 | 2.OG | Betonarbeiten | - | Türöffnung | 7506Köf0000000233 | m³ | AllplanAttributes - Object Layer Attributes #1, Attributset-Objekt: Door; Object Layer Attributes #1, DoorCommon, Barrierefrei: no; Object Layer Attributes #1, DoorCommon, Rauchschutz: no; Object Layer Attributes #1, DoorCommon, Selbstschließend: no; Object Layer Attributes #1, DoorCommon, Antrieb: no
 | 2.OG | Mauerarbeiten | DIN L | Türöffnung | 7506Köf0000000298 | m³ | no
 | 2.OG | Mauerarbeiten |  | Fensteröffnung | 7506Köf0000000314 | m³ | no
 | 2.OG | Betonarbeiten | DIN L | Türöffnung | 7506Köf0000000270 | m³ | AllplanAttributes - Object Layer Attributes #1, Attributset-Objekt: Door; Object Layer Attributes #1, DoorCommon, Barrierefrei: no; Object Layer Attributes #1, DoorCommon, Rauchschutz: no; Object Layer Attributes #1, DoorCommon, Selbstschließend: no; Object Layer Attributes #1, DoorCommon, Antrieb: no
 | 2.OG | Wärme- und Kältedämmarbeiten |  | Fensteröffnung | 7506Köf0000000259 | m² | no
 | 2.OG | Wärme- und Kältedämmarbeiten |  | Fensteröffnung | 7506Köf0000000262 | m² | no
 | 2.OG | Betonarbeiten | - | Türöffnung | 7506Köf0000000265 | m² | AllplanAttributes - Object Layer Attributes #1, Attributset-Objekt: Door; Object Layer Attributes #1, DoorCommon, Barrierefrei: no; Object Layer Attributes #1, DoorCommon, Rauchschutz: no; Object Layer Attributes #1, DoorCommon, Selbstschließend: no; Object Layer Attributes #1, DoorCommon, Antrieb: no
 | 2.OG | Mauerarbeiten | DIN R | Türöffnung | 7506Köf0000000065 | m³ | no | AllplanAttributes - Object Layer Attributes #1, Versatz_oben: 0; Object Layer Attributes #1, Versatz_unten: 0
 | 2.OG | Betonarbeiten | - | Türöffnung | 7506Köf0000000290 | m² | AllplanAttributes - Object Layer Attributes #1, Attributset-Objekt: Door; Object Layer Attributes #1, DoorCommon, Barrierefrei: no; Object Layer Attributes #1, DoorCommon, Rauchschutz: no; Object Layer Attributes #1, DoorCommon, Selbstschließend: no; Object Layer Attributes #1, DoorCommon, Antrieb: no
 | 2.OG | Wärme- und Kältedämmarbeiten |  | Fensteröffnung | 7506Köf0000000293 | m² | no
 | 2.OG | Mauerarbeiten | DIN L | Türöffnung | 7506Köf0000000086 | m³ | no | AllplanAttributes - Object Layer Attributes #1, Versatz_oben: 0; Object Layer Attributes #1, Versatz_unten: 0
 | 2.OG | Betonarbeiten | - | Türöffnung | 7506Köf0000000006 | m³ | AllplanAttributes - Object Layer Attributes #1, Attributset-Objekt: Door; Object Layer Attributes #1, DoorCommon, Barrierefrei: no; Object Layer Attributes #1, DoorCommon, Rauchschutz: no; Object Layer Attributes #1, DoorCommon, Selbstschließend: no; Object Layer Attributes #1, DoorCommon, Antrieb: no
 | 3.OG | Betonarbeiten | - | Türöffnung | 7507Köf0000000006 | m³ | AllplanAttributes - Object Layer Attributes #1, Attributset-Objekt: Door; Object Layer Attributes #1, DoorCommon, Barrierefrei: no; Object Layer Attributes #1, DoorCommon, Rauchschutz: no; Object Layer Attributes #1, DoorCommon, Selbstschließend: no; Object Layer Attributes #1, DoorCommon, Antrieb: no
 | 3.OG | Mauerarbeiten | DIN L | Türöffnung | 7507Köf0000000086 | m³ | no
 | 3.OG | Mauerarbeiten |  | Fensteröffnung | 7507Köf0000000104 | m³ | no
 | 3.OG | Betonarbeiten | DIN L | Türöffnung | 7507Köf0000000231 | m² | AllplanAttributes - Object Layer Attributes #1, Attributset-Objekt: Door; Object Layer Attributes #1, DoorCommon, Barrierefrei: no; Object Layer Attributes #1, DoorCommon, Rauchschutz: no; Object Layer Attributes #1, DoorCommon, Selbstschließend: no; Object Layer Attributes #1, DoorCommon, Antrieb: no
Deckendurchbruch | 3.OG | Betonarbeiten |  | Deckendurchbruch | 7507Das0000000333 | m² | no | AllplanAttributes - Object Layer Attributes #1, Bezeichnung: Deckendurchbruch
Deckendurchbruch | 3.OG | Betonarbeiten |  | Deckendurchbruch | 7507Das0000000332 | m² | no | AllplanAttributes - Object Layer Attributes #1, Bezeichnung: Deckendurchbruch
 | 3.OG | Mauerarbeiten | DIN L | Türöffnung | 7507Köf0000000199 | m³ | no
 | 3.OG | Mauerarbeiten |  | Fensteröffnung | 7507Köf0000000041 | m³ | no
 | 3.OG | Mauerarbeiten | DIN L | Türöffnung | 7507Köf0000000017 | m³ | no
 | 3.OG | Betonarbeiten |  | Fensteröffnung | 7507Köf0000000124 | m³ | no
 | 3.OG | Wärme- und Kältedämmarbeiten |  | Fensteröffnung | 7507Köf0000000185 | m² | no
 | 3.OG | Wärme- und Kältedämmarbeiten |  | Fensteröffnung | 7507Köf0000000078 | m² | no
 | 3.OG | Wärme- und Kältedämmarbeiten |  | Fensteröffnung | 7507Köf0000000081 | m² | no
 | 3.OG | Mauerarbeiten | DIN R | Türöffnung | 7507Köf0000000144 | m³ | no
 | 3.OG | Mauerarbeiten | DIN R | Türöffnung | 7507Köf0000000162 | m³ | no
 | 3.OG | Mauerarbeiten |  | Fensteröffnung | 7507Köf0000000052 | m³ | no

# IfcOpeningElement: Recess (12)
AllplanAttributes - Object Layer Attributes #1, Status: Neubau; Object Layer Attributes #1, Gewerk: Betonarbeiten; Object Layer Attributes #1, Objektname: Deckendurchbruch; Object Layer Attributes #1, Bezeichnung: Beton; Object Layer Attributes #1, Tragendes Bauteil: no; Object Layer Attributes #1, Abrechnungsart: m²
Pset_OpeningElementCommon - FireExit: no; ProtectedOpening: no
Name | In | Object Layer Attributes #1, Allright_Bauteil_ID
Beton | UG | 7503Das0000000244
Beton | UG | 7503Das0000000243
Beton | UG | 7503Das0000000253
Beton | EG | 7504Das0000000345
Beton | EG | 7504Das0000000344
Beton | EG | 7504Das0000000348
Beton | 1.OG | 7505Das0000000330
Beton | 1.OG | 7505Das0000000329
Beton | 1.OG | 7505Das0000000324
Beton | 2.OG | 7506Das0000000362
Beton | 2.OG | 7506Das0000000361
Beton | 2.OG | 7506Das0000000356

# IfcPile (2)
In: 3.OG
Material: Bois
AllplanAttributes - 2D Interaktion: yes; Gewerk: Zimmer- und Holzbauarbeiten; Objektname: Wand; Material: Bois; Attributset-Objekt: Pile; Außenbauteil: no; Traduction matériau: Bois; Abrechnungsart: m³
PileCommon - Status: Neubau; Tragendes Bauteil: yes
Name | Allright_Bauteil_ID
 | 7507Kop0000000269
 | 7507Kop0000000267

# IfcSlab (22)
AllplanAttributes - 2D Interaktion: yes; Abrechnungsart: m²
Pset_SlabCommon - LoadBearing: yes
Name | In | PredefinedType | Material = AllplanAttributes, Material = Traduction matériau | Gewerk | Objektname | Allright_Bauteil_ID | AllplanAttributes, Status | Combustible = Compartmentation
 | UG | BASESLAB | NPK 0 | Betonarbeiten | Unterlagsbeton | 7503PFu0000000003 | AllplanAttributes - Aussenbauteil: yes; Attributset-Objekt: Slab; SlabCommon - Status: Neubau
 | UG | BASESLAB | NPK 0 | Wärme- und Kältedämmarbeiten | Unterlagsbeton | 7503PFu0000000004 | AllplanAttributes - Aussenbauteil: yes; Attributset-Objekt: Slab; SlabCommon - Status: Neubau
 | UG | FLOOR | Béton | Betonarbeiten | Decke | 7503De 0000000242 | Neubau | no
 | UG | FLOOR | Béton | Betonarbeiten | Decke | 7503De 0000000248 | Neubau | no
 | UG | FLOOR | Béton | Betonarbeiten | Decke | 7503De 0000000250 | Neubau | no
 | UG | BASESLAB | Béton | Betonarbeiten | Plattenfundament | 7503PFu0000000002 | AllplanAttributes - Aussenbauteil: yes; Attributset-Objekt: Slab; SlabCommon - Status: Neubau
 | EG | FLOOR | Béton | Betonarbeiten | Decke | 7504De 0000000339 | Neubau | no
 | EG | FLOOR | Béton | Betonarbeiten | Decke | 7504De 0000000337 | Neubau | no
 | EG | FLOOR | Béton | Betonarbeiten | Decke | 7504De 0000000343 | Neubau | no
 | EG | FLOOR | Béton | Betonarbeiten | Decke | 7504De 0000000347 | Neubau | no
 | EG | FLOOR | Béton | Betonarbeiten | Decke | 7504De 0000000341 | Neubau | no
 | 1.OG | FLOOR | Béton | Betonarbeiten | Decke | 7505De 0000000328 | Neubau | no
 | 1.OG | FLOOR | Béton | Betonarbeiten | Decke | 7505De 0000000321 | Neubau | no
 | 1.OG | FLOOR | Béton | Betonarbeiten | Decke | 7505De 0000000323 | Neubau | no
 | 2.OG | FLOOR | Béton | Betonarbeiten | Decke | 7506De 0000000360 | Neubau | no
 | 2.OG | FLOOR | Béton | Betonarbeiten | Decke | 7506De 0000000355 | Neubau | no
 | 2.OG | FLOOR | Béton | Betonarbeiten | Decke | 7506De 0000000351 | Neubau | no
 | 2.OG | FLOOR | Béton | Betonarbeiten | Decke | 7506De 0000000353 | Neubau | no
 | 3.OG | FLOOR | Béton | Betonarbeiten | Decke | 7507De 0000000303 | Neubau | no
 | 3.OG | FLOOR | Béton | Betonarbeiten | Decke | 7507De 0000000331 | Neubau | no
 | 3.OG | FLOOR | Béton | Betonarbeiten | Decke | 7507Kop0000000340 |  | no | AllplanAttributes - Attributset-Objekt: Slab; Länge: 11.66 m; Dicke: 7.19 m; Höhe: 0.45 m; SlabCommon - Status: Neubau
 | 3.OG | FLOOR | Béton | Betonarbeiten | Decke | 7507De 0000000329 | Neubau | no

# IfcWall (54)
AllplanAttributes - 2D Interaktion: yes; Höhe: 0 m; Objektname: Wand; Attributset-Objekt: Wall
Pset_WallCommon - Combustible: no; Compartmentation: no; ExtendToStructure: no
WallCommon - Status: Neubau
Name | In | Material = AllplanAttributes, Material = Traduction matériau | Gewerk | Länge (m) | Dicke (m) | Außenbauteil | Allright_Bauteil_ID | Abrechnungsart | LoadBearing
 | UG | Brique silico-calcaire | Mauerarbeiten | 4.29 | 0.15 | yes | 7503Kop0000000015 | m³
Betonwand | UG | Béton | Betonarbeiten | 1.6 | 0.15 | yes | 7503Kop0000000234 | m³ | yes | AllplanAttributes - Bezeichnung: Betonwand; Aussenbauteil: no
Betonwand | UG | Béton | Betonarbeiten | 7.28 | 0.25 | yes | 7503Kop0000000010 | m³ | yes | AllplanAttributes - Bezeichnung: Betonwand; Aussenbauteil: no
 | UG | Brique silico-calcaire | Mauerarbeiten | 10.025 | 0.15 | yes | 7503Kop0000000119 | m³
 | UG | Brique silico-calcaire | Mauerarbeiten | 4.53 | 0.15 | yes | 7503Kop0000000045 | m³
 | UG | Brique silico-calcaire | Mauerarbeiten | 1.33 | 0.15 | yes | 7503Kop0000000202 | m³
Betonwand | UG | Béton | Betonarbeiten | 14.805 | 0.25 | yes | 7503Kop0000000108 | m³ | yes | AllplanAttributes - Bezeichnung: Betonwand; Aussenbauteil: no
Betonwand | UG | Béton | Betonarbeiten | 4.445 | 0.2 | yes | 7503Kop0000000178 | m³ | yes | AllplanAttributes - Bezeichnung: Betonwand; Aussenbauteil: no
 | UG | Brique silico-calcaire | Mauerarbeiten | 3.31 | 0.15 | yes | 7503Kop0000000078 | m³
Betonwand | EG | Béton | Betonarbeiten | 6.745 | 0.2 | yes | 7504Kop0000000014 | m³ | yes | AllplanAttributes - Bezeichnung: Betonwand; Aussenbauteil: no
 | EG | Isolation périphérique | Wärme- und Kältedämmarbeiten | 10.28 | 0.23 |  | 7504Kop0000000316 | m²
Betonwand | EG | Béton | Betonarbeiten | 1.6 | 0.15 | yes | 7504Kop0000000003 | m³ | yes | AllplanAttributes - Bezeichnung: Betonwand; Aussenbauteil: no
Betonwand | EG | Béton | Betonarbeiten | 10.05 | 0.18 | yes | 7504Kop0000000290 | m³ | yes | AllplanAttributes - Bezeichnung: Betonwand; Aussenbauteil: no
 | EG | Brique | Mauerarbeiten | 4.735 | 0.175 | yes | 7504Kop0000000038 | m³ | yes | AllplanAttributes - Abrechnungsart (2): St
 | EG | Isolation périphérique | Wärme- und Kältedämmarbeiten | 11.4 | 0.23 |  | 7504Kop0000000079 | m²
 | EG | Brique | Mauerarbeiten | 1.265 | 0.15 | yes | 7504Kop0000000202 | m³ | yes | AllplanAttributes - Abrechnungsart (2): St
 | EG | Brique | Mauerarbeiten | 11.48 | 0.175 | yes | 7504Kop0000000117 | m³ | yes | AllplanAttributes - Abrechnungsart (2): St
 | EG | Brique | Mauerarbeiten | 3.03 | 0.15 | yes | 7504Kop0000000096 | m³ | yes | AllplanAttributes - Abrechnungsart (2): St
 | EG | Isolation périphérique | Wärme- und Kältedämmarbeiten | 11.68 | 0.23 |  | 7504Kop0000000185 | m²
 | EG | Brique | Mauerarbeiten | 3.38 | 0.15 | yes | 7504Kop0000000223 | m³ | yes | AllplanAttributes - Abrechnungsart (2): St
Betonwand | EG | Béton | Betonarbeiten | 4.695 | 0.2 | yes | 7504Kop0000000263 | m³ | yes | AllplanAttributes - Bezeichnung: Betonwand; Aussenbauteil: no
 | 1.OG | Brique | Mauerarbeiten | 3.03 | 0.15 | yes | 7505Kop0000000123 | m³ | yes | AllplanAttributes - Abrechnungsart (2): St
Betonwand | 1.OG | Béton | Betonarbeiten | 4.695 | 0.2 | yes | 7505Kop0000000072 | m³ | yes | AllplanAttributes - Bezeichnung: Betonwand; Aussenbauteil: no
Betonwand | 1.OG | Béton | Betonarbeiten | 6.745 | 0.2 | yes | 7505Kop0000000014 | m³ | yes | AllplanAttributes - Bezeichnung: Betonwand; Aussenbauteil: no
Betonwand | 1.OG | Béton | Betonarbeiten | 1.6 | 0.15 | yes | 7505Kop0000000003 | m³ | yes | AllplanAttributes - Bezeichnung: Betonwand; Aussenbauteil: no
 | 1.OG | Brique | Mauerarbeiten | 3.38 | 0.15 | yes | 7505Kop0000000159 | m³ | yes | AllplanAttributes - Abrechnungsart (2): St
 | 1.OG | Isolation périphérique | Wärme- und Kältedämmarbeiten | 11.4 | 0.23 |  | 7505Kop0000000064 | m²
 | 1.OG | Brique | Mauerarbeiten | 4.735 | 0.175 | yes | 7505Kop0000000023 | m³ | yes | AllplanAttributes - Abrechnungsart (2): St
 | 1.OG | Brique | Mauerarbeiten | 11.48 | 0.175 | yes | 7505Kop0000000199 | m³ | yes | AllplanAttributes - Abrechnungsart (2): St
Betonwand | 1.OG | Béton | Betonarbeiten | 10.05 | 0.18 | yes | 7505Kop0000000284 | m³ | yes | AllplanAttributes - Bezeichnung: Betonwand; Aussenbauteil: no
 | 1.OG | Brique | Mauerarbeiten | 1.265 | 0.15 | yes | 7505Kop0000000102 | m³ | yes | AllplanAttributes - Abrechnungsart (2): St
 | 1.OG | Isolation périphérique | Wärme- und Kältedämmarbeiten | 11.68 | 0.23 |  | 7505Kop0000000273 | m²
Betonwand | 2.OG | Béton | Betonarbeiten | 4.695 | 0.2 | yes | 7506Kop0000000035 | m³ | yes | AllplanAttributes - Bezeichnung: Betonwand; Aussenbauteil: no
 | 2.OG | Brique | Mauerarbeiten | 3.38 | 0.15 | yes | 7506Kop0000000116 | m³ | yes | AllplanAttributes - Abrechnungsart (2): St
 | 2.OG | Brique | Mauerarbeiten | 4.74 | 0.175 | yes | 7506Kop0000000156 | m³ | yes | AllplanAttributes - Abrechnungsart (2): St
 | 2.OG | Brique | Mauerarbeiten | 11.485 | 0.175 | yes | 7506Kop0000000182 | m³ | yes | AllplanAttributes - Abrechnungsart (2): St
Betonwand | 2.OG | Béton | Mauerarbeiten | 10.05 | 0.175 | yes | 7506Kop0000000295 | m³ | yes | AllplanAttributes - Bezeichnung: Betonwand; Aussenbauteil: no
Betonwand | 2.OG | Béton | Betonarbeiten | 6.745 | 0.2 | yes | 7506Kop0000000267 | m³ | yes | AllplanAttributes - Bezeichnung: Betonwand; Aussenbauteil: no
 | 2.OG | Isolation périphérique | Wärme- und Kältedämmarbeiten | 11.68 | 0.23 |  | 7506Kop0000000256 | m²
 | 2.OG | Brique | Mauerarbeiten | 1.265 | 0.15 | yes | 7506Kop0000000062 | m³ | yes | AllplanAttributes - Abrechnungsart (2): St
 | 2.OG | Isolation périphérique | Wärme- und Kältedämmarbeiten | 11.4 | 0.23 |  | 7506Kop0000000287 | m²
 | 2.OG | Brique | Mauerarbeiten | 3.03 | 0.15 | yes | 7506Kop0000000083 | m³ | yes | AllplanAttributes - Abrechnungsart (2): St
Betonwand | 2.OG | Béton | Betonarbeiten | 1.6 | 0.15 | yes | 7506Kop0000000003 | m³ | yes | AllplanAttributes - Bezeichnung: Betonwand; Aussenbauteil: no
Betonwand | 3.OG | Béton | Betonarbeiten | 1.6 | 0.15 | yes | 7507Kop0000000003 | m³ | yes | AllplanAttributes - Bezeichnung: Betonwand; Aussenbauteil: no
Betonwand | 3.OG | Béton | Mauerarbeiten | 7.015 | 0.175 | yes | 7507Kop0000000083 | m³ | yes | AllplanAttributes - Bezeichnung: Betonwand; Aussenbauteil: no
 | 3.OG | Isolation périphérique | Wärme- und Kältedämmarbeiten | 2.86 | 0.23 |  | 7507Kop0000000228 | m² | no
Betonwand | 3.OG | Béton | Betonarbeiten | 1.23 | 0.2 | yes | 7507Kop0000000196 | m³ | yes | AllplanAttributes - Bezeichnung: Betonwand; Aussenbauteil: no
 | 3.OG | Brique | Mauerarbeiten | 2.05 | 0.15 | yes | 7507Kop0000000038 | m³ | yes | AllplanAttributes - Abrechnungsart (2): St
 | 3.OG | Brique | Mauerarbeiten | 1.06 | 0.15 | yes | 7507Kop0000000014 | m³ | yes | AllplanAttributes - Abrechnungsart (2): St
Betonwand | 3.OG | Béton | Betonarbeiten | 6.745 | 0.2 | yes | 7507Kop0000000121 | m³ | yes | AllplanAttributes - Bezeichnung: Betonwand; Aussenbauteil: no
 | 3.OG | Isolation périphérique | Wärme- und Kältedämmarbeiten | 3.77 | 0.23 |  | 7507Kop0000000182 | m²
 | 3.OG | Isolation périphérique | Wärme- und Kältedämmarbeiten | 11.4 | 0.23 |  | 7507Kop0000000075 | m²
 | 3.OG | Brique | Mauerarbeiten | 11.66 | 0.175 | yes | 7507Kop0000000141 | m³ | yes | AllplanAttributes - Abrechnungsart (2): St
 | 3.OG | Brique | Mauerarbeiten | 4.74 | 0.175 | yes | 7507Kop0000000049 | m³ | yes | AllplanAttributes - Abrechnungsart (2): St

# IfcWallStandardCase (85)
AllplanAttributes - Attributset-Objekt: Wall; Abrechnungsart: m³; Object Layer Attributes #1, 2D Interaktion: yes; Object Layer Attributes #1, Objektname: Wand
Pset_WallCommon - Combustible: no; Compartmentation: no; ExtendToStructure: no
WallCommon - Status: Neubau
Name | In | Material | Objektname | Allright_Bauteil_ID | Object Layer Attributes #1, Gewerk | Object Layer Attributes #1, Material = Object Layer Attributes #1, Traduction matériau | Object Layer Attributes #1, Attributset-Objekt | Object Layer Attributes #1, Außenbauteil | Object Layer Attributes #1, Allright_Bauteil_ID | Object Layer Attributes #1, Abrechnungsart | Object Layer Attributes #1, WallCommon, Status | Object Layer Attributes #1, WallCommon, Brennbares Material = Object Layer Attributes #1, WallCommon, Brandabschnittsdefinierendes Bauteil = Object Layer Attributes #1, WallCommon, Raumhohe Wand
 | UG | Brique silico-calcaire 0.15 m | Mehrsch-Wand | 7503HWa0000000011 | Mauerarbeiten | Brique silico-calcaire | Wall | yes | 7503Wa 0000000012 | m³ | Neubau | no
 | UG | Brique silico-calcaire 0.15 m | Mehrsch-Wand | 7503HWa0000000035 | Mauerarbeiten | Brique silico-calcaire | Wall | yes | 7503Wa 0000000036 | m³ | Neubau | no
 | UG | Brique silico-calcaire 0.15 m | Mehrsch-Wand | 7503HWa0000000038 | Mauerarbeiten | Brique silico-calcaire | Wall | yes | 7503Wa 0000000039 | m³ | Neubau | no
Betonwand | UG | Béton 0.25 m | Wand | 7503HWa0000000041 | Betonarbeiten | Béton | Wall | yes | 7503Wa 0000000042 | m³ | Neubau | no | AllplanAttributes - Bezeichnung: Betonwand; Aussenbauteil: no; Object Layer Attributes #1, WallCommon, Tragendes Bauteil: yes; Pset_WallCommon - LoadBearing: yes
Betonwand | UG | Béton 0.25 m | Wand | 7503HWa0000000065 | Betonarbeiten | Béton | Wall | yes | 7503Wa 0000000066 | m³ | Neubau | no | AllplanAttributes - Bezeichnung: Betonwand; Aussenbauteil: no; Object Layer Attributes #1, WallCommon, Tragendes Bauteil: yes; Pset_WallCommon - LoadBearing: yes
 | UG | Isolation périphérique 0.22 m | Wand | 7503HWa0000000068 | Wärme- und Kältedämmarbeiten | Isolation périphérique |  |  | 7503Wa 0000000069 | m² | AllplanAttributes - Object Layer Attributes #1, Status: Neubau; Object Layer Attributes #1, Tragendes Bauteil: no
 | UG | Isolation périphérique 0.22 m | Wand | 7503HWa0000000071 | Wärme- und Kältedämmarbeiten | Isolation périphérique |  |  | 7503Wa 0000000072 | m² | AllplanAttributes - Object Layer Attributes #1, Status: Neubau; Object Layer Attributes #1, Tragendes Bauteil: no
 | UG | Isolation périphérique 0.22 m | Wand | 7503HWa0000000074 | Wärme- und Kältedämmarbeiten | Isolation périphérique |  |  | 7503Wa 0000000075 | m² | AllplanAttributes - Object Layer Attributes #1, Status: Neubau; Object Layer Attributes #1, Tragendes Bauteil: no
 | UG | Brique silico-calcaire 0.15 m | Mehrsch-Wand | 7503HWa0000000098 | Mauerarbeiten | Brique silico-calcaire | Wall | yes | 7503Wa 0000000099 | m³ | Neubau | no
Betonwand | UG | Béton 0.2 m | Wand | 7503HWa0000000101 | Betonarbeiten | Béton | Wall | yes | 7503Wa 0000000102 | m³ | Neubau | no | AllplanAttributes - Bezeichnung: Betonwand; Aussenbauteil: no; Object Layer Attributes #1, WallCommon, Tragendes Bauteil: yes; Pset_WallCommon - LoadBearing: yes
Betonwand | UG | Béton 0.25 m | Wand | 7503HWa0000000104 | Betonarbeiten | Béton | Wall | yes | 7503Wa 0000000105 | m³ | Neubau | no | AllplanAttributes - Bezeichnung: Betonwand; Aussenbauteil: no; Pset_WallCommon - LoadBearing: yes
Betonwand | UG | Béton 0.2 m | Wand | 7503HWa0000000109 | Betonarbeiten | Béton | Wall | yes | 7503Wa 0000000110 | m³ | Neubau | no | AllplanAttributes - Bezeichnung: Betonwand; Aussenbauteil: no; Object Layer Attributes #1, WallCommon, Tragendes Bauteil: yes; Pset_WallCommon - LoadBearing: yes
 | UG | Brique silico-calcaire 0.15 m | Mehrsch-Wand | 7503HWa0000000112 | Mauerarbeiten | Brique silico-calcaire | Wall | yes | 7503Wa 0000000113 | m³ | Neubau | no
 | UG | Brique silico-calcaire 0.15 m | Mehrsch-Wand | 7503HWa0000000115 | Mauerarbeiten | Brique silico-calcaire | Wall | yes | 7503Wa 0000000116 | m³ | Neubau | no
 | UG | Isolation périphérique 0.22 m | Wand | 7503HWa0000000198 | Wärme- und Kältedämmarbeiten | Isolation périphérique |  |  | 7503Wa 0000000199 | m² | AllplanAttributes - Object Layer Attributes #1, Status: Neubau; Object Layer Attributes #1, Tragendes Bauteil: no
 | UG | Isolation périphérique 0.22 m | Wand | 7503HWa0000000222 | Wärme- und Kältedämmarbeiten | Isolation périphérique |  |  | 7503Wa 0000000223 | m² | AllplanAttributes - Object Layer Attributes #1, Status: Neubau; Object Layer Attributes #1, Tragendes Bauteil: no
Betonwand | UG | Béton 0.25 m | Wand | 7503HWa0000000238 | Betonarbeiten | Béton | Wall | yes | 7503Wa 0000000239 | m³ | Neubau | no | AllplanAttributes - Bezeichnung: Betonwand; Aussenbauteil: no; Object Layer Attributes #1, WallCommon, Tragendes Bauteil: yes; Pset_WallCommon - LoadBearing: yes
Betonwand | EG | Béton 0.25 m | Wand | 7504HWa0000000007 | Betonarbeiten | Béton | Wall | yes | 7504Wa 0000000008 | m³ | Neubau | no | AllplanAttributes - Bezeichnung: Betonwand; Aussenbauteil: no; Pset_WallCommon - LoadBearing: yes
Betonwand | EG | Béton 0.2 m | Wand | 7504HWa0000000010 | Betonarbeiten | Béton | Wall | yes | 7504Wa 0000000011 | m³ | Neubau | no | AllplanAttributes - Bezeichnung: Betonwand; Aussenbauteil: no; Pset_WallCommon - LoadBearing: yes
 | EG | Brique 0.15 m | Mehrsch-Wand | 7504HWa0000000063 | Mauerarbeiten | Brique | Wall | yes | 7504Wa 0000000064 | m³ | Neubau | no | AllplanAttributes - Object Layer Attributes #1, WallCommon, Tragendes Bauteil: yes; Abrechnungsart (2): St
 | EG | Brique 0.15 m | Mehrsch-Wand | 7504HWa0000000066 | Mauerarbeiten | Brique | Wall | yes | 7504Wa 0000000067 | m³ | Neubau | no | AllplanAttributes - Object Layer Attributes #1, WallCommon, Tragendes Bauteil: yes; Abrechnungsart (2): St
Betonwand | EG | Béton 0.2 m | Wand | 7504HWa0000000069 | Betonarbeiten | Béton | Wall | yes | 7504Wa 0000000070 | m³ | Neubau | no | AllplanAttributes - Bezeichnung: Betonwand; Aussenbauteil: no; Pset_WallCommon - LoadBearing: yes
 | EG | Brique 0.15 m | Mehrsch-Wand | 7504HWa0000000072 | Mauerarbeiten | Brique | Wall | yes | 7504Wa 0000000073 | m³ | Neubau | no | AllplanAttributes - Object Layer Attributes #1, WallCommon, Tragendes Bauteil: yes; Abrechnungsart (2): St
 | EG | Isolation périphérique 0.13 m | Wand | 7504HWa0000000075 | Wärme- und Kältedämmarbeiten | Isolation périphérique |  |  | 7504Wa 0000000076 | m² | AllplanAttributes - Object Layer Attributes #1, Status: Neubau
 | EG | Isolation périphérique 0.13 m | Wand | 7504HWa0000000086 | Wärme- und Kältedämmarbeiten | Isolation périphérique |  |  | 7504Wa 0000000087 | m² | AllplanAttributes - Object Layer Attributes #1, Status: Neubau
 | EG | Brique 0.15 m | Mehrsch-Wand | 7504HWa0000000089 | Mauerarbeiten | Brique | Wall | yes | 7504Wa 0000000090 | m³ | Neubau | no | AllplanAttributes - Object Layer Attributes #1, WallCommon, Tragendes Bauteil: yes; Abrechnungsart (2): St
 | EG | Brique 0.15 m | Mehrsch-Wand | 7504HWa0000000092 | Mauerarbeiten | Brique | Wall | yes | 7504Wa 0000000093 | m³ | Neubau | no | AllplanAttributes - Object Layer Attributes #1, WallCommon, Tragendes Bauteil: yes; Abrechnungsart (2): St
 | EG | Brique 0.15 m | Mehrsch-Wand | 7504HWa0000000195 | Mauerarbeiten | Brique | Wall | yes | 7504Wa 0000000196 | m³ | Neubau | no | AllplanAttributes - Object Layer Attributes #1, WallCommon, Tragendes Bauteil: yes; Abrechnungsart (2): St
 | EG | Brique 0.175 m | Mehrsch-Wand | 7504HWa0000000198 | Mauerarbeiten | Brique | Wall | yes | 7504Wa 0000000199 | m³ | Neubau | no | AllplanAttributes - Object Layer Attributes #1, WallCommon, Tragendes Bauteil: yes; Abrechnungsart (2): St
 | EG | Brique 0.15 m | Mehrsch-Wand | 7504HWa0000000283 | Mauerarbeiten | Brique | Wall | yes | 7504Wa 0000000284 | m³ | Neubau | no | AllplanAttributes - Object Layer Attributes #1, WallCommon, Tragendes Bauteil: yes; Abrechnungsart (2): St
 | EG | Brique 0.15 m | Mehrsch-Wand | 7504HWa0000000286 | Mauerarbeiten | Brique | Wall | yes | 7504Wa 0000000287 | m³ | Neubau | no | AllplanAttributes - Object Layer Attributes #1, WallCommon, Tragendes Bauteil: yes; Abrechnungsart (2): St
 | EG | Brique 0.175 m | Mehrsch-Wand | 7504HWa0000000320 | Mauerarbeiten | Brique | Wall | yes | 7504Wa 0000000321 | m³ | Neubau | no | AllplanAttributes - Object Layer Attributes #1, WallCommon, Tragendes Bauteil: yes; Abrechnungsart (2): St
 | EG | Isolation périphérique 0.04 m | Wand | 7504HWa0000000331 | Wärme- und Kältedämmarbeiten | Isolation périphérique |  |  | 7504Wa 0000000332 | m² | AllplanAttributes - Object Layer Attributes #1, Status: Neubau
Betonwand | 1.OG | Béton 0.25 m | Wand | 7505HWa0000000007 | Betonarbeiten | Béton | Wall | yes | 7505Wa 0000000008 | m³ | Neubau | no | AllplanAttributes - Bezeichnung: Betonwand; Aussenbauteil: no; Pset_WallCommon - LoadBearing: yes
Betonwand | 1.OG | Béton 0.2 m | Wand | 7505HWa0000000010 | Betonarbeiten | Béton | Wall | yes | 7505Wa 0000000011 | m³ | Neubau | no | AllplanAttributes - Bezeichnung: Betonwand; Aussenbauteil: no; Pset_WallCommon - LoadBearing: yes
 | 1.OG | Brique 0.15 m | Mehrsch-Wand | 7505HWa0000000048 | Mauerarbeiten | Brique | Wall | yes | 7505Wa 0000000049 | m³ | Neubau | no | AllplanAttributes - Object Layer Attributes #1, WallCommon, Tragendes Bauteil: yes; Abrechnungsart (2): St
 | 1.OG | Brique 0.15 m | Mehrsch-Wand | 7505HWa0000000051 | Mauerarbeiten | Brique | Wall | yes | 7505Wa 0000000052 | m³ | Neubau | no | AllplanAttributes - Object Layer Attributes #1, WallCommon, Tragendes Bauteil: yes; Abrechnungsart (2): St
Betonwand | 1.OG | Béton 0.2 m | Wand | 7505HWa0000000054 | Betonarbeiten | Béton | Wall | yes | 7505Wa 0000000055 | m³ | Neubau | no | AllplanAttributes - Bezeichnung: Betonwand; Aussenbauteil: no; Pset_WallCommon - LoadBearing: yes
 | 1.OG | Brique 0.15 m | Mehrsch-Wand | 7505HWa0000000057 | Mauerarbeiten | Brique | Wall | yes | 7505Wa 0000000058 | m³ | Neubau | no | AllplanAttributes - Object Layer Attributes #1, WallCommon, Tragendes Bauteil: yes; Abrechnungsart (2): St
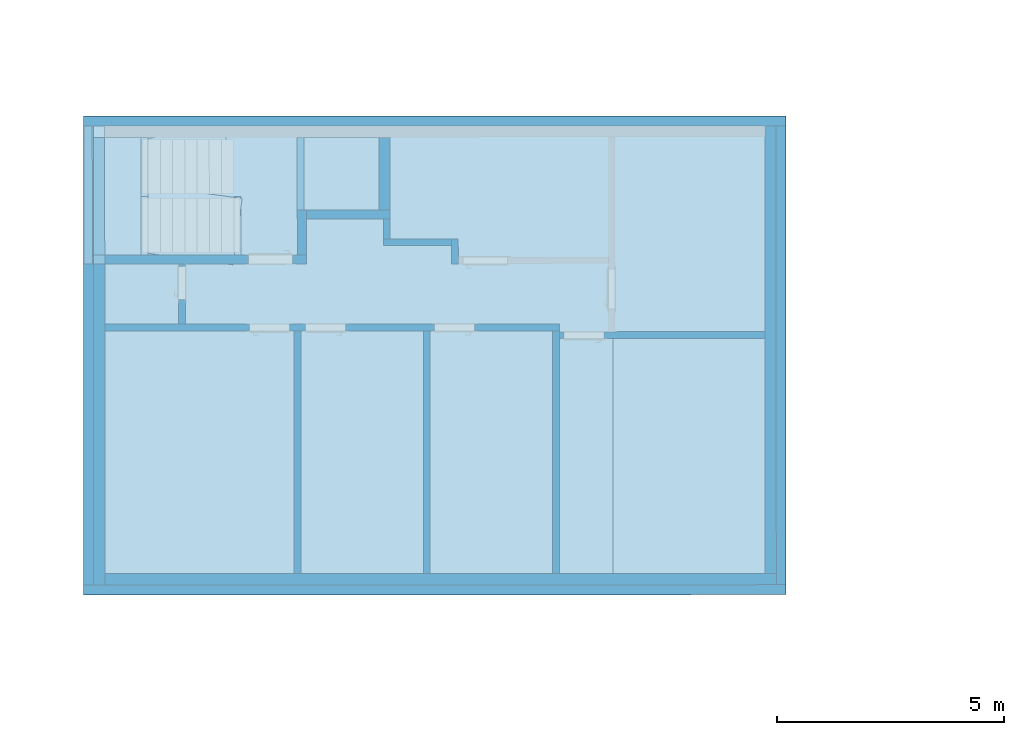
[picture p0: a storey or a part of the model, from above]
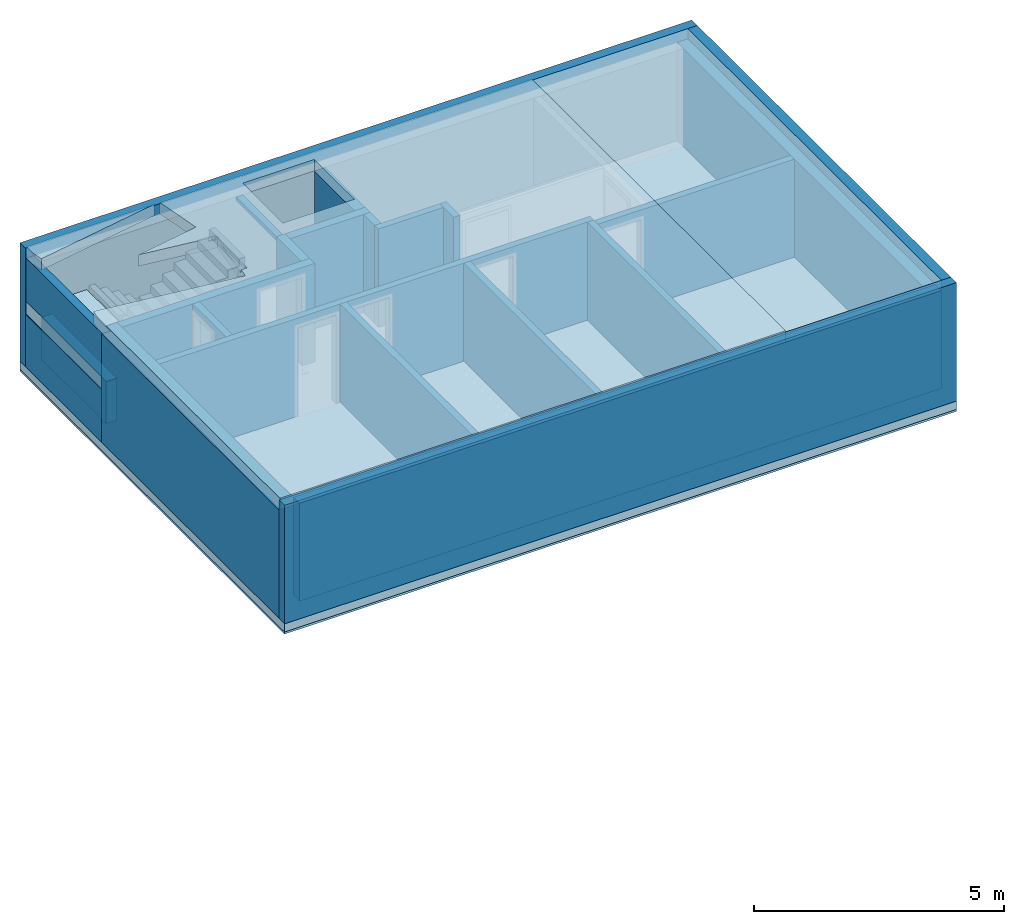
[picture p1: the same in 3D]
Properties of the parts of a building model (IFC2X3), part 2 of 2

# IfcWallStandardCase (85)
Name | In | Material | Objektname | Allright_Bauteil_ID | Object Layer Attributes #1, Gewerk | Object Layer Attributes #1, Material = Object Layer Attributes #1, Traduction matériau | Object Layer Attributes #1, Attributset-Objekt | Object Layer Attributes #1, Außenbauteil | Object Layer Attributes #1, Allright_Bauteil_ID | Object Layer Attributes #1, Abrechnungsart | Object Layer Attributes #1, WallCommon, Status | Object Layer Attributes #1, WallCommon, Brennbares Material = Object Layer Attributes #1, WallCommon, Brandabschnittsdefinierendes Bauteil = Object Layer Attributes #1, WallCommon, Raumhohe Wand
 | 1.OG | Isolation périphérique 0.13 m | Wand | 7505HWa0000000060 | Wärme- und Kältedämmarbeiten | Isolation périphérique |  |  | 7505Wa 0000000061 | m² | AllplanAttributes - Object Layer Attributes #1, Status: Neubau
 | 1.OG | Brique 0.15 m | Mehrsch-Wand | 7505HWa0000000092 | Mauerarbeiten | Brique | Wall | yes | 7505Wa 0000000093 | m³ | Neubau | no | AllplanAttributes - Object Layer Attributes #1, WallCommon, Tragendes Bauteil: yes; Abrechnungsart (2): St
 | 1.OG | Brique 0.15 m | Mehrsch-Wand | 7505HWa0000000095 | Mauerarbeiten | Brique | Wall | yes | 7505Wa 0000000096 | m³ | Neubau | no | AllplanAttributes - Object Layer Attributes #1, WallCommon, Tragendes Bauteil: yes; Abrechnungsart (2): St
 | 1.OG | Brique 0.15 m | Mehrsch-Wand | 7505HWa0000000098 | Mauerarbeiten | Brique | Wall | yes | 7505Wa 0000000099 | m³ | Neubau | no | AllplanAttributes - Object Layer Attributes #1, WallCommon, Tragendes Bauteil: yes; Abrechnungsart (2): St
 | 1.OG | Isolation périphérique 0.04 m | Wand | 7505HWa0000000143 | Wärme- und Kältedämmarbeiten | Isolation périphérique |  |  | 7505Wa 0000000144 | m² | AllplanAttributes - Object Layer Attributes #1, Status: Neubau
 | 1.OG | Isolation périphérique 0.13 m | Wand | 7505HWa0000000146 | Wärme- und Kältedämmarbeiten | Isolation périphérique |  |  | 7505Wa 0000000147 | m² | AllplanAttributes - Object Layer Attributes #1, Status: Neubau
 | 1.OG | Brique 0.175 m | Mehrsch-Wand | 7505HWa0000000149 | Mauerarbeiten | Brique | Wall | yes | 7505Wa 0000000150 | m³ | Neubau | no | AllplanAttributes - Object Layer Attributes #1, WallCommon, Tragendes Bauteil: yes; Abrechnungsart (2): St
 | 1.OG | Brique 0.15 m | Mehrsch-Wand | 7505HWa0000000152 | Mauerarbeiten | Brique | Wall | yes | 7505Wa 0000000153 | m³ | Neubau | no | AllplanAttributes - Object Layer Attributes #1, WallCommon, Tragendes Bauteil: yes; Abrechnungsart (2): St
 | 1.OG | Brique 0.15 m | Mehrsch-Wand | 7505HWa0000000155 | Mauerarbeiten | Brique | Wall | yes | 7505Wa 0000000156 | m³ | Neubau | no | AllplanAttributes - Object Layer Attributes #1, WallCommon, Tragendes Bauteil: yes; Abrechnungsart (2): St
 | 1.OG | Isolation périphérique 0.23 m | Wand | 7505HWa0000000303 | Wärme- und Kältedämmarbeiten | Isolation périphérique |  |  | 7505Wa 0000000304 | m² | AllplanAttributes - Object Layer Attributes #1, Status: Neubau
 | 1.OG | Isolation périphérique 0.23 m | Wand | 7505HWa0000000306 | Wärme- und Kältedämmarbeiten | Isolation périphérique |  |  | 7505Wa 0000000307 | m² | AllplanAttributes - Object Layer Attributes #1, Status: Neubau
 | 1.OG | Brique 0.175 m | Mehrsch-Wand | 7505HWa0000000317 | Mauerarbeiten | Brique | Wall | yes | 7505Wa 0000000318 | m³ | Neubau | no | AllplanAttributes - Object Layer Attributes #1, WallCommon, Tragendes Bauteil: yes; Abrechnungsart (2): St
Betonwand | 2.OG | Béton 0.25 m | Wand | 7506HWa0000000007 | Betonarbeiten | Béton | Wall | yes | 7506Wa 0000000008 | m³ | Neubau | no | AllplanAttributes - Bezeichnung: Betonwand; Aussenbauteil: no; Pset_WallCommon - LoadBearing: yes
Betonwand | 2.OG | Béton 0.2 m | Wand | 7506HWa0000000010 | Betonarbeiten | Béton | Wall | yes | 7506Wa 0000000011 | m³ | Neubau | no | AllplanAttributes - Bezeichnung: Betonwand; Aussenbauteil: no; Pset_WallCommon - LoadBearing: yes
 | 2.OG | Brique 0.15 m | Mehrsch-Wand | 7506HWa0000000013 | Mauerarbeiten | Brique | Wall | yes | 7506Wa 0000000014 | m³ | Neubau | no | AllplanAttributes - Object Layer Attributes #1, WallCommon, Tragendes Bauteil: yes; Abrechnungsart (2): St
 | 2.OG | Brique 0.15 m | Mehrsch-Wand | 7506HWa0000000016 | Mauerarbeiten | Brique | Wall | yes | 7506Wa 0000000017 | m³ | Neubau | no | AllplanAttributes - Object Layer Attributes #1, WallCommon, Tragendes Bauteil: yes; Abrechnungsart (2): St
Betonwand | 2.OG | Béton 0.2 m | Wand | 7506HWa0000000019 | Betonarbeiten | Béton | Wall | yes | 7506Wa 0000000020 | m³ | Neubau | no | AllplanAttributes - Bezeichnung: Betonwand; Aussenbauteil: no; Pset_WallCommon - LoadBearing: yes
 | 2.OG | Brique 0.15 m | Mehrsch-Wand | 7506HWa0000000022 | Mauerarbeiten | Brique | Wall | yes | 7506Wa 0000000023 | m³ | Neubau | no | AllplanAttributes - Object Layer Attributes #1, WallCommon, Tragendes Bauteil: yes; Abrechnungsart (2): St
 | 2.OG | Isolation périphérique 0.13 m | Wand | 7506HWa0000000025 | Wärme- und Kältedämmarbeiten | Isolation périphérique |  |  | 7506Wa 0000000026 | m² | AllplanAttributes - Object Layer Attributes #1, Status: Neubau
 | 2.OG | Isolation périphérique 0.04 m | Wand | 7506HWa0000000028 | Wärme- und Kältedämmarbeiten | Isolation périphérique |  |  | 7506Wa 0000000029 | m² | AllplanAttributes - Object Layer Attributes #1, Status: Neubau
 | 2.OG | Isolation périphérique 0.13 m | Wand | 7506HWa0000000031 | Wärme- und Kältedämmarbeiten | Isolation périphérique |  |  | 7506Wa 0000000032 | m² | AllplanAttributes - Object Layer Attributes #1, Status: Neubau
 | 2.OG | Brique 0.15 m | Mehrsch-Wand | 7506HWa0000000055 | Mauerarbeiten | Brique | Wall | yes | 7506Wa 0000000056 | m³ | Neubau | no | AllplanAttributes - Object Layer Attributes #1, WallCommon, Tragendes Bauteil: yes; Abrechnungsart (2): St
 | 2.OG | Brique 0.15 m | Mehrsch-Wand | 7506HWa0000000058 | Mauerarbeiten | Brique | Wall | yes | 7506Wa 0000000059 | m³ | Neubau | no | AllplanAttributes - Object Layer Attributes #1, WallCommon, Tragendes Bauteil: yes; Abrechnungsart (2): St
 | 2.OG | Brique 0.15 m | Mehrsch-Wand | 7506HWa0000000103 | Mauerarbeiten | Brique | Wall | yes | 7506Wa 0000000104 | m³ | Neubau | no | AllplanAttributes - Object Layer Attributes #1, WallCommon, Tragendes Bauteil: yes; Abrechnungsart (2): St
 | 2.OG | Brique 0.15 m | Mehrsch-Wand | 7506HWa0000000106 | Mauerarbeiten | Brique | Wall | yes | 7506Wa 0000000107 | m³ | Neubau | no | AllplanAttributes - Object Layer Attributes #1, WallCommon, Tragendes Bauteil: yes; Abrechnungsart (2): St
 | 2.OG | Brique 0.15 m | Mehrsch-Wand | 7506HWa0000000109 | Mauerarbeiten | Brique | Wall | yes | 7506Wa 0000000110 | m³ | Neubau | no | AllplanAttributes - Object Layer Attributes #1, WallCommon, Tragendes Bauteil: yes; Abrechnungsart (2): St
 | 2.OG | Brique 0.175 m | Mehrsch-Wand | 7506HWa0000000112 | Mauerarbeiten | Brique | Wall | yes | 7506Wa 0000000113 | m³ | Neubau | no | AllplanAttributes - Object Layer Attributes #1, WallCommon, Tragendes Bauteil: yes; Abrechnungsart (2): St
 | 2.OG | Isolation périphérique 0.23 m | Wand | 7506HWa0000000330 | Wärme- und Kältedämmarbeiten | Isolation périphérique |  |  | 7506Wa 0000000331 | m² | AllplanAttributes - Object Layer Attributes #1, Status: Neubau
 | 2.OG | Isolation périphérique 0.23 m | Wand | 7506HWa0000000333 | Wärme- und Kältedämmarbeiten | Isolation périphérique |  |  | 7506Wa 0000000334 | m² | AllplanAttributes - Object Layer Attributes #1, Status: Neubau
 | 2.OG | Isolation périphérique 0.23 m | Wand | 7506HWa0000000336 | Wärme- und Kältedämmarbeiten | Isolation périphérique |  |  | 7506Wa 0000000337 | m² | AllplanAttributes - Object Layer Attributes #1, Status: Neubau
 | 2.OG | Brique 0.175 m | Mehrsch-Wand | 7506HWa0000000343 | Mauerarbeiten | Brique | Wall | yes | 7506Wa 0000000344 | m³ | Neubau | no | AllplanAttributes - Object Layer Attributes #1, WallCommon, Tragendes Bauteil: yes; Abrechnungsart (2): St
Betonwand | 3.OG | Béton 0.25 m | Wand | 7507HWa0000000007 | Betonarbeiten | Béton | Wall | yes | 7507Wa 0000000008 | m³ | Neubau | no | AllplanAttributes - Bezeichnung: Betonwand; Aussenbauteil: no; Pset_WallCommon - LoadBearing: yes
Betonwand | 3.OG | Béton 0.2 m | Wand | 7507HWa0000000010 | Betonarbeiten | Béton | Wall | yes | 7507Wa 0000000011 | m³ | Neubau | no | AllplanAttributes - Bezeichnung: Betonwand; Aussenbauteil: no; Pset_WallCommon - LoadBearing: yes
 | 3.OG | Isolation périphérique 0.13 m | Wand | 7507HWa0000000034 | Wärme- und Kältedämmarbeiten | Isolation périphérique |  |  | 7507Wa 0000000035 | m² | AllplanAttributes - Object Layer Attributes #1, Status: Neubau
 | 3.OG | Brique 0.15 m | Mehrsch-Wand | 7507HWa0000000045 | Mauerarbeiten | Brique | Wall | yes | 7507Wa 0000000046 | m³ | Neubau | no | AllplanAttributes - Object Layer Attributes #1, WallCommon, Tragendes Bauteil: yes; Abrechnungsart (2): St
 | 3.OG | Isolation périphérique 0.23 m | Wand | 7507HWa0000000178 | Wärme- und Kältedämmarbeiten | Isolation périphérique |  |  | 7507Wa 0000000179 | m² | AllplanAttributes - Object Layer Attributes #1, Status: Neubau
 | 3.OG | Isolation périphérique 0.23 m | Wand | 7507HWa0000000186 | Wärme- und Kältedämmarbeiten | Isolation périphérique |  |  | 7507Wa 0000000187 | m² | AllplanAttributes - Object Layer Attributes #1, Status: Neubau
 | 3.OG | Isolation périphérique 0.23 m | Wand | 7507HWa0000000189 | Wärme- und Kältedämmarbeiten | Isolation périphérique |  |  | 7507Wa 0000000190 | m² | AllplanAttributes - Object Layer Attributes #1, Status: Neubau
 | 3.OG | Isolation périphérique 0.23 m | Wand | 7507HWa0000000192 | Wärme- und Kältedämmarbeiten | Isolation périphérique |  |  | 7507Wa 0000000193 | m² | AllplanAttributes - Object Layer Attributes #1, Status: Neubau
Betonwand | 3.OG | Béton 0.2 m | Wand | 7507HWa0000000219 | Betonarbeiten | Béton | Wall | yes | 7507Wa 0000000220 | m³ | Neubau | no | AllplanAttributes - Bezeichnung: Betonwand; Aussenbauteil: no; Pset_WallCommon - LoadBearing: yes
Betonwand | 3.OG | Béton 0.2 m | Wand | 7507HWa0000000222 | Betonarbeiten | Béton | Wall | yes | 7507Wa 0000000223 | m³ | Neubau | no | AllplanAttributes - Bezeichnung: Betonwand; Aussenbauteil: no; Object Layer Attributes #1, WallCommon, Tragendes Bauteil: no; Pset_WallCommon - LoadBearing: yes
 | 3.OG | Isolation périphérique 0.23 m | Wand | 7507HWa0000000248 | Wärme- und Kältedämmarbeiten | Isolation périphérique |  |  | 7507Wa 0000000249 | m² | AllplanAttributes - Object Layer Attributes #1, Status: Neubau; Object Layer Attributes #1, Tragendes Bauteil: no
 | 3.OG | Isolation périphérique 0.04 m | Wand | 7507HWa0000000251 | Wärme- und Kältedämmarbeiten | Isolation périphérique |  |  | 7507Wa 0000000252 | m² | AllplanAttributes - Object Layer Attributes #1, Status: Neubau
 | 3.OG | Brique 0.175 m | Mehrsch-Wand | 7507HWa0000000254 | Mauerarbeiten | Brique | Wall | yes | 7507Wa 0000000255 | m³ | Neubau | no | AllplanAttributes - Object Layer Attributes #1, WallCommon, Tragendes Bauteil: yes; Abrechnungsart (2): St
 | 3.OG | Isolation périphérique 0.13 m | Wand | 7507HWa0000000257 | Wärme- und Kältedämmarbeiten | Isolation périphérique |  |  | 7507Wa 0000000258 | m² | AllplanAttributes - Object Layer Attributes #1, Status: Neubau
 | 3.OG | Brique 0.175 m | Mehrsch-Wand | 7507HWa0000000263 | Mauerarbeiten | Brique | Wall | yes | 7507Wa 0000000264 | m³ | Neubau | no | AllplanAttributes - Object Layer Attributes #1, WallCommon, Tragendes Bauteil: yes; Abrechnungsart (2): St

# IfcWindow: H50 Lichth. Rund
In: 3.OG
Type - OperationType: USERDEFINED; ParameterTakesPrecedence: no; Sizeable: no
OverallHeight: 1.14 m; OverallWidth: 1.14 m
AllplanAttributes (H50 Lichth. Rund) - V6: 0 m; V7: 0 m; V8: 0 m; V9: 0; Programmversion: 2.2; Objektname: Deckendurchbruchsmakro; Bezeichnung: H50 Lichth. Rund; Plugin_Bezeichnung: MainObject; Plugin_Objektname: SmartPartCompressed; Version: 2.1; Lichtkuppel_Kranzhöhe: 0.71 m; Lichtkuppel_Höhe_Lichthaube: 0.26 m; Attributset-Objekt: Window; Abrechnungsart (2): St; Allright_Bauteil_ID: 7507Mak0000000338; Abrechnungsart: St
